VERSION 5.7 ;
  NOWIREEXTENSIONATPIN ON ;
  DIVIDERCHAR "/" ;
  BUSBITCHARS "[]" ;
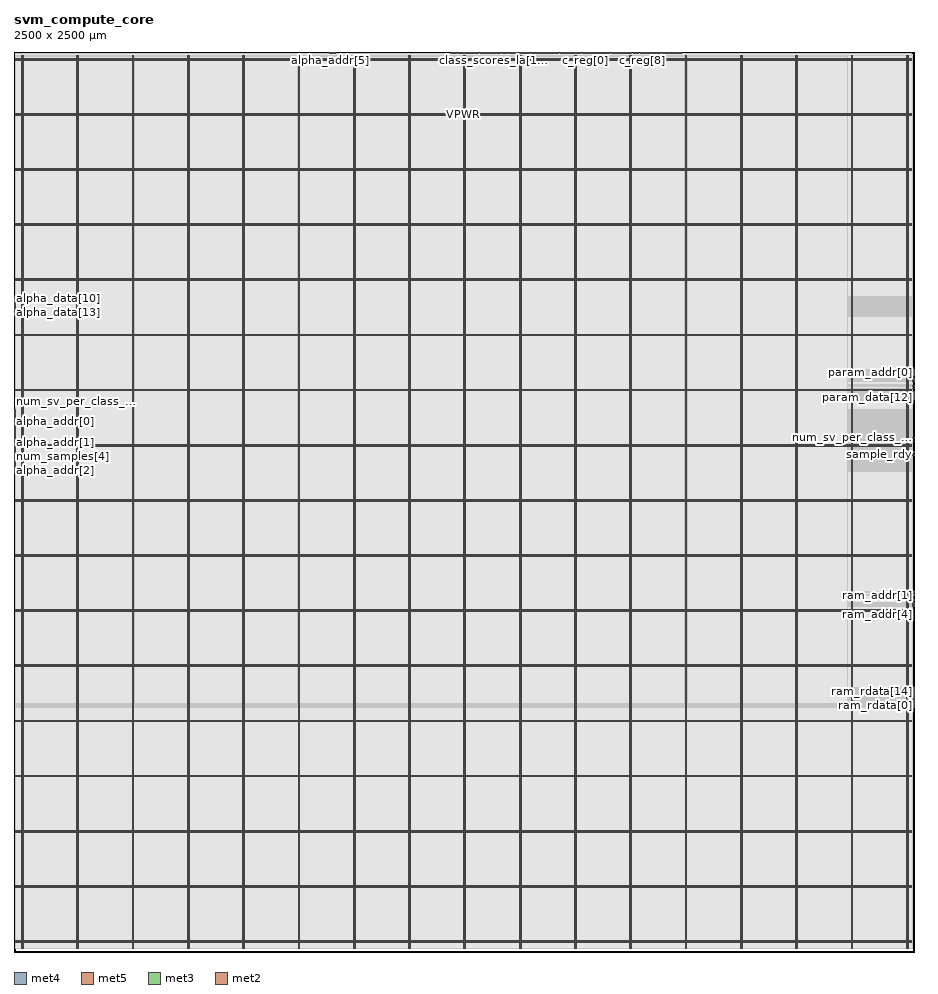
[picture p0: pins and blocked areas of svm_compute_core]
MACRO svm_compute_core
  CLASS BLOCK ;
  FOREIGN svm_compute_core ;
  ORIGIN 0.000 0.000 ;
  SIZE 2500.000 BY 2500.000 ;
  PIN VGND
    DIRECTION INOUT ;
    USE GROUND ;
    PORT
      LAYER met4 ;
        RECT 24.340 10.640 25.940 2489.040 ;
    END
    PORT
      LAYER met4 ;
        RECT 177.940 10.640 179.540 2489.040 ;
    END
    PORT
      LAYER met4 ;
        RECT 331.540 10.640 333.140 2489.040 ;
    END
    PORT
      LAYER met4 ;
        RECT 485.140 10.640 486.740 2489.040 ;
    END
    PORT
      LAYER met4 ;
        RECT 638.740 10.640 640.340 2489.040 ;
    END
    PORT
      LAYER met4 ;
        RECT 792.340 10.640 793.940 2489.040 ;
    END
    PORT
      LAYER met4 ;
        RECT 945.940 10.640 947.540 2489.040 ;
    END
    PORT
      LAYER met4 ;
        RECT 1099.540 10.640 1101.140 2489.040 ;
    END
    PORT
      LAYER met4 ;
        RECT 1253.140 10.640 1254.740 2489.040 ;
    END
    PORT
      LAYER met4 ;
        RECT 1406.740 10.640 1408.340 2489.040 ;
    END
    PORT
      LAYER met4 ;
        RECT 1560.340 10.640 1561.940 2489.040 ;
    END
    PORT
      LAYER met4 ;
        RECT 1713.940 10.640 1715.540 2489.040 ;
    END
    PORT
      LAYER met4 ;
        RECT 1867.540 10.640 1869.140 2489.040 ;
    END
    PORT
      LAYER met4 ;
        RECT 2021.140 10.640 2022.740 2489.040 ;
    END
    PORT
      LAYER met4 ;
        RECT 2174.740 10.640 2176.340 2489.040 ;
    END
    PORT
      LAYER met4 ;
        RECT 2328.340 10.640 2329.940 2489.040 ;
    END
    PORT
      LAYER met4 ;
        RECT 2481.940 10.640 2483.540 2489.040 ;
    END
    PORT
      LAYER met5 ;
        RECT 5.280 30.030 2494.360 31.630 ;
    END
    PORT
      LAYER met5 ;
        RECT 5.280 183.210 2494.360 184.810 ;
    END
    PORT
      LAYER met5 ;
        RECT 5.280 336.390 2494.360 337.990 ;
    END
    PORT
      LAYER met5 ;
        RECT 5.280 489.570 2494.360 491.170 ;
    END
    PORT
      LAYER met5 ;
        RECT 5.280 642.750 2494.360 644.350 ;
    END
    PORT
      LAYER met5 ;
        RECT 5.280 795.930 2494.360 797.530 ;
    END
    PORT
      LAYER met5 ;
        RECT 5.280 949.110 2494.360 950.710 ;
    END
    PORT
      LAYER met5 ;
        RECT 5.280 1102.290 2494.360 1103.890 ;
    END
    PORT
      LAYER met5 ;
        RECT 5.280 1255.470 2494.360 1257.070 ;
    END
    PORT
      LAYER met5 ;
        RECT 5.280 1408.650 2494.360 1410.250 ;
    END
    PORT
      LAYER met5 ;
        RECT 5.280 1561.830 2494.360 1563.430 ;
    END
    PORT
      LAYER met5 ;
        RECT 5.280 1715.010 2494.360 1716.610 ;
    END
    PORT
      LAYER met5 ;
        RECT 5.280 1868.190 2494.360 1869.790 ;
    END
    PORT
      LAYER met5 ;
        RECT 5.280 2021.370 2494.360 2022.970 ;
    END
    PORT
      LAYER met5 ;
        RECT 5.280 2174.550 2494.360 2176.150 ;
    END
    PORT
      LAYER met5 ;
        RECT 5.280 2327.730 2494.360 2329.330 ;
    END
    PORT
      LAYER met5 ;
        RECT 5.280 2480.910 2494.360 2482.510 ;
    END
  END VGND
  PIN VPWR
    DIRECTION INOUT ;
    USE POWER ;
    PORT
      LAYER met4 ;
        RECT 21.040 10.640 22.640 2489.040 ;
    END
    PORT
      LAYER met4 ;
        RECT 174.640 10.640 176.240 2489.040 ;
    END
    PORT
      LAYER met4 ;
        RECT 328.240 10.640 329.840 2489.040 ;
    END
    PORT
      LAYER met4 ;
        RECT 481.840 10.640 483.440 2489.040 ;
    END
    PORT
      LAYER met4 ;
        RECT 635.440 10.640 637.040 2489.040 ;
    END
    PORT
      LAYER met4 ;
        RECT 789.040 10.640 790.640 2489.040 ;
    END
    PORT
      LAYER met4 ;
        RECT 942.640 10.640 944.240 2489.040 ;
    END
    PORT
      LAYER met4 ;
        RECT 1096.240 10.640 1097.840 2489.040 ;
    END
    PORT
      LAYER met4 ;
        RECT 1249.840 10.640 1251.440 2489.040 ;
    END
    PORT
      LAYER met4 ;
        RECT 1403.440 10.640 1405.040 2489.040 ;
    END
    PORT
      LAYER met4 ;
        RECT 1557.040 10.640 1558.640 2489.040 ;
    END
    PORT
      LAYER met4 ;
        RECT 1710.640 10.640 1712.240 2489.040 ;
    END
    PORT
      LAYER met4 ;
        RECT 1864.240 10.640 1865.840 2489.040 ;
    END
    PORT
      LAYER met4 ;
        RECT 2017.840 10.640 2019.440 2489.040 ;
    END
    PORT
      LAYER met4 ;
        RECT 2171.440 10.640 2173.040 2489.040 ;
    END
    PORT
      LAYER met4 ;
        RECT 2325.040 10.640 2326.640 2489.040 ;
    END
    PORT
      LAYER met4 ;
        RECT 2478.640 10.640 2480.240 2489.040 ;
    END
    PORT
      LAYER met5 ;
        RECT 5.280 26.730 2494.360 28.330 ;
    END
    PORT
      LAYER met5 ;
        RECT 5.280 179.910 2494.360 181.510 ;
    END
    PORT
      LAYER met5 ;
        RECT 5.280 333.090 2494.360 334.690 ;
    END
    PORT
      LAYER met5 ;
        RECT 5.280 486.270 2494.360 487.870 ;
    END
    PORT
      LAYER met5 ;
        RECT 5.280 639.450 2494.360 641.050 ;
    END
    PORT
      LAYER met5 ;
        RECT 5.280 792.630 2494.360 794.230 ;
    END
    PORT
      LAYER met5 ;
        RECT 5.280 945.810 2494.360 947.410 ;
    END
    PORT
      LAYER met5 ;
        RECT 5.280 1098.990 2494.360 1100.590 ;
    END
    PORT
      LAYER met5 ;
        RECT 5.280 1252.170 2494.360 1253.770 ;
    END
    PORT
      LAYER met5 ;
        RECT 5.280 1405.350 2494.360 1406.950 ;
    END
    PORT
      LAYER met5 ;
        RECT 5.280 1558.530 2494.360 1560.130 ;
    END
    PORT
      LAYER met5 ;
        RECT 5.280 1711.710 2494.360 1713.310 ;
    END
    PORT
      LAYER met5 ;
        RECT 5.280 1864.890 2494.360 1866.490 ;
    END
    PORT
      LAYER met5 ;
        RECT 5.280 2018.070 2494.360 2019.670 ;
    END
    PORT
      LAYER met5 ;
        RECT 5.280 2171.250 2494.360 2172.850 ;
    END
    PORT
      LAYER met5 ;
        RECT 5.280 2324.430 2494.360 2326.030 ;
    END
    PORT
      LAYER met5 ;
        RECT 5.280 2477.610 2494.360 2479.210 ;
    END
  END VPWR
  PIN alpha_addr[0]
    DIRECTION INPUT ;
    USE SIGNAL ;
    ANTENNAGATEAREA 0.990000 ;
    PORT
      LAYER met3 ;
        RECT 0.000 1472.240 4.000 1472.840 ;
    END
  END alpha_addr[0]
  PIN alpha_addr[1]
    DIRECTION INPUT ;
    USE SIGNAL ;
    ANTENNAGATEAREA 0.990000 ;
    PORT
      LAYER met3 ;
        RECT 0.000 1414.440 4.000 1415.040 ;
    END
  END alpha_addr[1]
  PIN alpha_addr[2]
    DIRECTION INPUT ;
    USE SIGNAL ;
    ANTENNAGATEAREA 0.990000 ;
    PORT
      LAYER met3 ;
        RECT 0.000 1336.240 4.000 1336.840 ;
    END
  END alpha_addr[2]
  PIN alpha_addr[3]
    DIRECTION INPUT ;
    USE SIGNAL ;
    ANTENNAGATEAREA 0.990000 ;
    PORT
      LAYER met3 ;
        RECT 0.000 1356.640 4.000 1357.240 ;
    END
  END alpha_addr[3]
  PIN alpha_addr[4]
    DIRECTION INPUT ;
    USE SIGNAL ;
    ANTENNAGATEAREA 0.742500 ;
    PORT
      LAYER met2 ;
        RECT 875.930 2496.000 876.210 2500.000 ;
    END
  END alpha_addr[4]
  PIN alpha_addr[5]
    DIRECTION INPUT ;
    USE SIGNAL ;
    ANTENNAGATEAREA 0.742500 ;
    PORT
      LAYER met2 ;
        RECT 879.150 2496.000 879.430 2500.000 ;
    END
  END alpha_addr[5]
  PIN alpha_addr[6]
    DIRECTION INPUT ;
    USE SIGNAL ;
    ANTENNAGATEAREA 0.742500 ;
    PORT
      LAYER met2 ;
        RECT 892.030 2496.000 892.310 2500.000 ;
    END
  END alpha_addr[6]
  PIN alpha_addr[7]
    DIRECTION INPUT ;
    USE SIGNAL ;
    ANTENNAGATEAREA 0.742500 ;
    PORT
      LAYER met2 ;
        RECT 888.810 2496.000 889.090 2500.000 ;
    END
  END alpha_addr[7]
  PIN alpha_addr[8]
    DIRECTION INPUT ;
    USE SIGNAL ;
    ANTENNAGATEAREA 0.247500 ;
    PORT
      LAYER met2 ;
        RECT 882.370 2496.000 882.650 2500.000 ;
    END
  END alpha_addr[8]
  PIN alpha_data[0]
    DIRECTION INPUT ;
    USE SIGNAL ;
    ANTENNAGATEAREA 0.852000 ;
    PORT
      LAYER met3 ;
        RECT 0.000 1819.040 4.000 1819.640 ;
    END
  END alpha_data[0]
  PIN alpha_data[10]
    DIRECTION INPUT ;
    USE SIGNAL ;
    ANTENNAGATEAREA 0.990000 ;
    PORT
      LAYER met3 ;
        RECT 0.000 1815.640 4.000 1816.240 ;
    END
  END alpha_data[10]
  PIN alpha_data[11]
    DIRECTION INPUT ;
    USE SIGNAL ;
    ANTENNAGATEAREA 0.990000 ;
    PORT
      LAYER met3 ;
        RECT 0.000 1812.240 4.000 1812.840 ;
    END
  END alpha_data[11]
  PIN alpha_data[12]
    DIRECTION INPUT ;
    USE SIGNAL ;
    ANTENNAGATEAREA 0.852000 ;
    PORT
      LAYER met3 ;
        RECT 0.000 1808.840 4.000 1809.440 ;
    END
  END alpha_data[12]
  PIN alpha_data[13]
    DIRECTION INPUT ;
    USE SIGNAL ;
    ANTENNAGATEAREA 0.495000 ;
    PORT
      LAYER met3 ;
        RECT 0.000 1798.640 4.000 1799.240 ;
    END
  END alpha_data[13]
  PIN alpha_data[14]
    DIRECTION INPUT ;
    USE SIGNAL ;
    ANTENNAGATEAREA 0.852000 ;
    PORT
      LAYER met3 ;
        RECT 0.000 1805.440 4.000 1806.040 ;
    END
  END alpha_data[14]
  PIN alpha_data[15]
    DIRECTION INPUT ;
    USE SIGNAL ;
    ANTENNAGATEAREA 0.990000 ;
    PORT
      LAYER met3 ;
        RECT 0.000 1802.040 4.000 1802.640 ;
    END
  END alpha_data[15]
  PIN alpha_data[1]
    DIRECTION INPUT ;
    USE SIGNAL ;
    ANTENNAGATEAREA 0.990000 ;
    PORT
      LAYER met3 ;
        RECT 0.000 1795.240 4.000 1795.840 ;
    END
  END alpha_data[1]
  PIN alpha_data[2]
    DIRECTION INPUT ;
    USE SIGNAL ;
    ANTENNAGATEAREA 0.990000 ;
    PORT
      LAYER met3 ;
        RECT 0.000 1791.840 4.000 1792.440 ;
    END
  END alpha_data[2]
  PIN alpha_data[3]
    DIRECTION INPUT ;
    USE SIGNAL ;
    ANTENNAGATEAREA 0.990000 ;
    PORT
      LAYER met3 ;
        RECT 0.000 1788.440 4.000 1789.040 ;
    END
  END alpha_data[3]
  PIN alpha_data[4]
    DIRECTION INPUT ;
    USE SIGNAL ;
    ANTENNAGATEAREA 0.990000 ;
    PORT
      LAYER met3 ;
        RECT 0.000 1785.040 4.000 1785.640 ;
    END
  END alpha_data[4]
  PIN alpha_data[5]
    DIRECTION INPUT ;
    USE SIGNAL ;
    ANTENNAGATEAREA 0.990000 ;
    PORT
      LAYER met3 ;
        RECT 0.000 1781.640 4.000 1782.240 ;
    END
  END alpha_data[5]
  PIN alpha_data[6]
    DIRECTION INPUT ;
    USE SIGNAL ;
    ANTENNAGATEAREA 0.990000 ;
    PORT
      LAYER met3 ;
        RECT 0.000 1778.240 4.000 1778.840 ;
    END
  END alpha_data[6]
  PIN alpha_data[7]
    DIRECTION INPUT ;
    USE SIGNAL ;
    ANTENNAGATEAREA 0.990000 ;
    PORT
      LAYER met3 ;
        RECT 0.000 1774.840 4.000 1775.440 ;
    END
  END alpha_data[7]
  PIN alpha_data[8]
    DIRECTION INPUT ;
    USE SIGNAL ;
    ANTENNAGATEAREA 0.247500 ;
    PORT
      LAYER met3 ;
        RECT 0.000 1771.440 4.000 1772.040 ;
    END
  END alpha_data[8]
  PIN alpha_data[9]
    DIRECTION INPUT ;
    USE SIGNAL ;
    ANTENNAGATEAREA 0.852000 ;
    PORT
      LAYER met3 ;
        RECT 0.000 1768.040 4.000 1768.640 ;
    END
  END alpha_data[9]
  PIN alpha_write_en
    DIRECTION INPUT ;
    USE SIGNAL ;
    ANTENNAGATEAREA 0.247500 ;
    PORT
      LAYER met2 ;
        RECT 885.590 2496.000 885.870 2500.000 ;
    END
  END alpha_write_en
  PIN c_reg[0]
    DIRECTION OUTPUT ;
    USE SIGNAL ;
    ANTENNADIFFAREA 0.340600 ;
    PORT
      LAYER met2 ;
        RECT 1587.550 2496.000 1587.830 2500.000 ;
    END
  END c_reg[0]
  PIN c_reg[10]
    DIRECTION OUTPUT ;
    USE SIGNAL ;
    ANTENNADIFFAREA 0.340600 ;
    PORT
      LAYER met2 ;
        RECT 1742.110 2496.000 1742.390 2500.000 ;
    END
  END c_reg[10]
  PIN c_reg[11]
    DIRECTION OUTPUT ;
    USE SIGNAL ;
    ANTENNADIFFAREA 0.340600 ;
    PORT
      LAYER met2 ;
        RECT 1526.370 2496.000 1526.650 2500.000 ;
    END
  END c_reg[11]
  PIN c_reg[12]
    DIRECTION OUTPUT ;
    USE SIGNAL ;
    ANTENNADIFFAREA 0.340600 ;
    PORT
      LAYER met2 ;
        RECT 1548.910 2496.000 1549.190 2500.000 ;
    END
  END c_reg[12]
  PIN c_reg[13]
    DIRECTION OUTPUT ;
    USE SIGNAL ;
    ANTENNADIFFAREA 0.340600 ;
    PORT
      LAYER met2 ;
        RECT 1523.150 2496.000 1523.430 2500.000 ;
    END
  END c_reg[13]
  PIN c_reg[14]
    DIRECTION OUTPUT ;
    USE SIGNAL ;
    ANTENNADIFFAREA 0.340600 ;
    PORT
      LAYER met2 ;
        RECT 1661.610 2496.000 1661.890 2500.000 ;
    END
  END c_reg[14]
  PIN c_reg[15]
    DIRECTION OUTPUT ;
    USE SIGNAL ;
    ANTENNADIFFAREA 0.340600 ;
    PORT
      LAYER met2 ;
        RECT 1703.470 2496.000 1703.750 2500.000 ;
    END
  END c_reg[15]
  PIN c_reg[1]
    DIRECTION OUTPUT ;
    USE SIGNAL ;
    ANTENNADIFFAREA 0.340600 ;
    PORT
      LAYER met2 ;
        RECT 1536.030 2496.000 1536.310 2500.000 ;
    END
  END c_reg[1]
  PIN c_reg[2]
    DIRECTION OUTPUT ;
    USE SIGNAL ;
    ANTENNADIFFAREA 0.340600 ;
    PORT
      LAYER met2 ;
        RECT 1529.590 2496.000 1529.870 2500.000 ;
    END
  END c_reg[2]
  PIN c_reg[3]
    DIRECTION OUTPUT ;
    USE SIGNAL ;
    ANTENNADIFFAREA 0.340600 ;
    PORT
      LAYER met2 ;
        RECT 1532.810 2496.000 1533.090 2500.000 ;
    END
  END c_reg[3]
  PIN c_reg[4]
    DIRECTION OUTPUT ;
    USE SIGNAL ;
    ANTENNADIFFAREA 0.340600 ;
    PORT
      LAYER met2 ;
        RECT 1716.350 2496.000 1716.630 2500.000 ;
    END
  END c_reg[4]
  PIN c_reg[5]
    DIRECTION OUTPUT ;
    USE SIGNAL ;
    ANTENNADIFFAREA 0.340600 ;
    PORT
      LAYER met2 ;
        RECT 1674.490 2496.000 1674.770 2500.000 ;
    END
  END c_reg[5]
  PIN c_reg[6]
    DIRECTION OUTPUT ;
    USE SIGNAL ;
    ANTENNADIFFAREA 0.340600 ;
    PORT
      LAYER met2 ;
        RECT 1568.230 2496.000 1568.510 2500.000 ;
    END
  END c_reg[6]
  PIN c_reg[7]
    DIRECTION OUTPUT ;
    USE SIGNAL ;
    ANTENNADIFFAREA 0.340600 ;
    PORT
      LAYER met2 ;
        RECT 1722.790 2496.000 1723.070 2500.000 ;
    END
  END c_reg[7]
  PIN c_reg[8]
    DIRECTION OUTPUT ;
    USE SIGNAL ;
    ANTENNADIFFAREA 0.340600 ;
    PORT
      LAYER met2 ;
        RECT 1745.330 2496.000 1745.610 2500.000 ;
    END
  END c_reg[8]
  PIN c_reg[9]
    DIRECTION OUTPUT ;
    USE SIGNAL ;
    ANTENNADIFFAREA 0.340600 ;
    PORT
      LAYER met2 ;
        RECT 1726.010 2496.000 1726.290 2500.000 ;
    END
  END c_reg[9]
  PIN class_out[0]
    DIRECTION OUTPUT ;
    USE SIGNAL ;
    ANTENNADIFFAREA 0.340600 ;
    PORT
      LAYER met2 ;
        RECT 1680.930 2496.000 1681.210 2500.000 ;
    END
  END class_out[0]
  PIN class_out[1]
    DIRECTION OUTPUT ;
    USE SIGNAL ;
    ANTENNADIFFAREA 0.340600 ;
    PORT
      LAYER met2 ;
        RECT 1465.190 2496.000 1465.470 2500.000 ;
    END
  END class_out[1]
  PIN class_out[2]
    DIRECTION OUTPUT ;
    USE SIGNAL ;
    ANTENNADIFFAREA 0.340600 ;
    PORT
      LAYER met2 ;
        RECT 1468.410 2496.000 1468.690 2500.000 ;
    END
  END class_out[2]
  PIN class_scores_la[0]
    DIRECTION OUTPUT ;
    USE SIGNAL ;
    ANTENNADIFFAREA 0.340600 ;
    PORT
      LAYER met2 ;
        RECT 1658.390 2496.000 1658.670 2500.000 ;
    END
  END class_scores_la[0]
  PIN class_scores_la[100]
    DIRECTION OUTPUT ;
    USE SIGNAL ;
    ANTENNADIFFAREA 0.340600 ;
    PORT
      LAYER met2 ;
        RECT 1539.250 2496.000 1539.530 2500.000 ;
    END
  END class_scores_la[100]
  PIN class_scores_la[101]
    DIRECTION OUTPUT ;
    USE SIGNAL ;
    ANTENNADIFFAREA 0.340600 ;
    PORT
      LAYER met2 ;
        RECT 1664.830 2496.000 1665.110 2500.000 ;
    END
  END class_scores_la[101]
  PIN class_scores_la[102]
    DIRECTION OUTPUT ;
    USE SIGNAL ;
    ANTENNADIFFAREA 0.340600 ;
    PORT
      LAYER met2 ;
        RECT 1478.070 2496.000 1478.350 2500.000 ;
    END
  END class_scores_la[102]
  PIN class_scores_la[103]
    DIRECTION OUTPUT ;
    USE SIGNAL ;
    ANTENNADIFFAREA 0.340600 ;
    PORT
      LAYER met2 ;
        RECT 1439.430 2496.000 1439.710 2500.000 ;
    END
  END class_scores_la[103]
  PIN class_scores_la[104]
    DIRECTION OUTPUT ;
    USE SIGNAL ;
    ANTENNADIFFAREA 0.340600 ;
    PORT
      LAYER met2 ;
        RECT 1848.370 2496.000 1848.650 2500.000 ;
    END
  END class_scores_la[104]
  PIN class_scores_la[105]
    DIRECTION OUTPUT ;
    USE SIGNAL ;
    ANTENNADIFFAREA 0.340600 ;
    PORT
      LAYER met2 ;
        RECT 1835.490 2496.000 1835.770 2500.000 ;
    END
  END class_scores_la[105]
  PIN class_scores_la[106]
    DIRECTION OUTPUT ;
    USE SIGNAL ;
    ANTENNADIFFAREA 0.340600 ;
    PORT
      LAYER met2 ;
        RECT 1622.970 2496.000 1623.250 2500.000 ;
    END
  END class_scores_la[106]
  PIN class_scores_la[107]
    DIRECTION OUTPUT ;
    USE SIGNAL ;
    ANTENNADIFFAREA 0.340600 ;
    PORT
      LAYER met2 ;
        RECT 1487.730 2496.000 1488.010 2500.000 ;
    END
  END class_scores_la[107]
  PIN class_scores_la[108]
    DIRECTION OUTPUT ;
    USE SIGNAL ;
    ANTENNADIFFAREA 0.340600 ;
    PORT
      LAYER met2 ;
        RECT 1442.650 2496.000 1442.930 2500.000 ;
    END
  END class_scores_la[108]
  PIN class_scores_la[109]
    DIRECTION OUTPUT ;
    USE SIGNAL ;
    ANTENNADIFFAREA 0.340600 ;
    PORT
      LAYER met2 ;
        RECT 1484.510 2496.000 1484.790 2500.000 ;
    END
  END class_scores_la[109]
  PIN class_scores_la[10]
    DIRECTION OUTPUT ;
    USE SIGNAL ;
    ANTENNADIFFAREA 0.340600 ;
    PORT
      LAYER met2 ;
        RECT 1635.850 2496.000 1636.130 2500.000 ;
    END
  END class_scores_la[10]
  PIN class_scores_la[110]
    DIRECTION OUTPUT ;
    USE SIGNAL ;
    ANTENNADIFFAREA 0.340600 ;
    PORT
      LAYER met2 ;
        RECT 1423.330 2496.000 1423.610 2500.000 ;
    END
  END class_scores_la[110]
  PIN class_scores_la[111]
    DIRECTION OUTPUT ;
    USE SIGNAL ;
    ANTENNADIFFAREA 0.340600 ;
    PORT
      LAYER met2 ;
        RECT 1394.350 2496.000 1394.630 2500.000 ;
    END
  END class_scores_la[111]
  PIN class_scores_la[112]
    DIRECTION OUTPUT ;
    USE SIGNAL ;
    ANTENNADIFFAREA 0.340600 ;
    PORT
      LAYER met2 ;
        RECT 1774.310 2496.000 1774.590 2500.000 ;
    END
  END class_scores_la[112]
  PIN class_scores_la[113]
    DIRECTION OUTPUT ;
    USE SIGNAL ;
    ANTENNADIFFAREA 0.340600 ;
    PORT
      LAYER met2 ;
        RECT 1404.010 2496.000 1404.290 2500.000 ;
    END
  END class_scores_la[113]
  PIN class_scores_la[114]
    DIRECTION OUTPUT ;
    USE SIGNAL ;
    ANTENNADIFFAREA 0.340600 ;
    PORT
      LAYER met2 ;
        RECT 1387.910 2496.000 1388.190 2500.000 ;
    END
  END class_scores_la[114]
  PIN class_scores_la[115]
    DIRECTION OUTPUT ;
    USE SIGNAL ;
    ANTENNADIFFAREA 0.340600 ;
    PORT
      LAYER met2 ;
        RECT 1333.170 2496.000 1333.450 2500.000 ;
    END
  END class_scores_la[115]
  PIN class_scores_la[116]
    DIRECTION OUTPUT ;
    USE SIGNAL ;
    ANTENNADIFFAREA 0.340600 ;
    PORT
      LAYER met2 ;
        RECT 1365.370 2496.000 1365.650 2500.000 ;
    END
  END class_scores_la[116]
  PIN class_scores_la[117]
    DIRECTION OUTPUT ;
    USE SIGNAL ;
    ANTENNADIFFAREA 0.340600 ;
    PORT
      LAYER met2 ;
        RECT 1416.890 2496.000 1417.170 2500.000 ;
    END
  END class_scores_la[117]
  PIN class_scores_la[118]
    DIRECTION OUTPUT ;
    USE SIGNAL ;
    ANTENNADIFFAREA 0.340600 ;
    PORT
      LAYER met2 ;
        RECT 1429.770 2496.000 1430.050 2500.000 ;
    END
  END class_scores_la[118]
  PIN class_scores_la[119]
    DIRECTION OUTPUT ;
    USE SIGNAL ;
    ANTENNADIFFAREA 0.340600 ;
    PORT
      LAYER met2 ;
        RECT 1436.210 2496.000 1436.490 2500.000 ;
    END
  END class_scores_la[119]
  PIN class_scores_la[11]
    DIRECTION OUTPUT ;
    USE SIGNAL ;
    ANTENNADIFFAREA 0.340600 ;
    PORT
      LAYER met2 ;
        RECT 1494.170 2496.000 1494.450 2500.000 ;
    END
  END class_scores_la[11]
  PIN class_scores_la[120]
    DIRECTION OUTPUT ;
    USE SIGNAL ;
    ANTENNADIFFAREA 0.340600 ;
    PORT
      LAYER met2 ;
        RECT 1452.310 2496.000 1452.590 2500.000 ;
    END
  END class_scores_la[120]
  PIN class_scores_la[121]
    DIRECTION OUTPUT ;
    USE SIGNAL ;
    ANTENNADIFFAREA 0.340600 ;
    PORT
      LAYER met2 ;
        RECT 1632.630 2496.000 1632.910 2500.000 ;
    END
  END class_scores_la[121]
  PIN class_scores_la[122]
    DIRECTION OUTPUT ;
    USE SIGNAL ;
    ANTENNADIFFAREA 0.340600 ;
    PORT
      LAYER met2 ;
        RECT 1796.850 2496.000 1797.130 2500.000 ;
    END
  END class_scores_la[122]
  PIN class_scores_la[123]
    DIRECTION OUTPUT ;
    USE SIGNAL ;
    ANTENNADIFFAREA 0.340600 ;
    PORT
      LAYER met2 ;
        RECT 1581.110 2496.000 1581.390 2500.000 ;
    END
  END class_scores_la[123]
  PIN class_scores_la[124]
    DIRECTION OUTPUT ;
    USE SIGNAL ;
    ANTENNADIFFAREA 0.340600 ;
    PORT
      LAYER met2 ;
        RECT 1790.410 2496.000 1790.690 2500.000 ;
    END
  END class_scores_la[124]
  PIN class_scores_la[125]
    DIRECTION OUTPUT ;
    USE SIGNAL ;
    ANTENNADIFFAREA 0.340600 ;
    PORT
      LAYER met2 ;
        RECT 1571.450 2496.000 1571.730 2500.000 ;
    END
  END class_scores_la[125]
  PIN class_scores_la[126]
    DIRECTION OUTPUT ;
    USE SIGNAL ;
    ANTENNADIFFAREA 0.340600 ;
    PORT
      LAYER met2 ;
        RECT 1764.650 2496.000 1764.930 2500.000 ;
    END
  END class_scores_la[126]
  PIN class_scores_la[127]
    DIRECTION OUTPUT ;
    USE SIGNAL ;
    ANTENNADIFFAREA 0.340600 ;
    PORT
      LAYER met2 ;
        RECT 1626.190 2496.000 1626.470 2500.000 ;
    END
  END class_scores_la[127]
  PIN class_scores_la[12]
    DIRECTION OUTPUT ;
    USE SIGNAL ;
    ANTENNADIFFAREA 0.340600 ;
    PORT
      LAYER met2 ;
        RECT 1713.130 2496.000 1713.410 2500.000 ;
    END
  END class_scores_la[12]
  PIN class_scores_la[13]
    DIRECTION OUTPUT ;
    USE SIGNAL ;
    ANTENNADIFFAREA 0.340600 ;
    PORT
      LAYER met2 ;
        RECT 1648.730 2496.000 1649.010 2500.000 ;
    END
  END class_scores_la[13]
  PIN class_scores_la[14]
    DIRECTION OUTPUT ;
    USE SIGNAL ;
    ANTENNADIFFAREA 0.340600 ;
    PORT
      LAYER met2 ;
        RECT 1458.750 2496.000 1459.030 2500.000 ;
    END
  END class_scores_la[14]
  PIN class_scores_la[15]
    DIRECTION OUTPUT ;
    USE SIGNAL ;
    ANTENNADIFFAREA 0.340600 ;
    PORT
      LAYER met2 ;
        RECT 1577.890 2496.000 1578.170 2500.000 ;
    END
  END class_scores_la[15]
  PIN class_scores_la[16]
    DIRECTION OUTPUT ;
    USE SIGNAL ;
    ANTENNADIFFAREA 0.340600 ;
    PORT
      LAYER met2 ;
        RECT 1825.830 2496.000 1826.110 2500.000 ;
    END
  END class_scores_la[16]
  PIN class_scores_la[17]
    DIRECTION OUTPUT ;
    USE SIGNAL ;
    ANTENNADIFFAREA 0.340600 ;
    PORT
      LAYER met2 ;
        RECT 1259.110 2496.000 1259.390 2500.000 ;
    END
  END class_scores_la[17]
  PIN class_scores_la[18]
    DIRECTION OUTPUT ;
    USE SIGNAL ;
    ANTENNADIFFAREA 0.340600 ;
    PORT
      LAYER met2 ;
        RECT 1339.610 2496.000 1339.890 2500.000 ;
    END
  END class_scores_la[18]
  PIN class_scores_la[19]
    DIRECTION OUTPUT ;
    USE SIGNAL ;
    ANTENNADIFFAREA 0.340600 ;
    PORT
      LAYER met2 ;
        RECT 1384.690 2496.000 1384.970 2500.000 ;
    END
  END class_scores_la[19]
  PIN class_scores_la[1]
    DIRECTION OUTPUT ;
    USE SIGNAL ;
    ANTENNADIFFAREA 0.340600 ;
    PORT
      LAYER met2 ;
        RECT 1461.970 2496.000 1462.250 2500.000 ;
    END
  END class_scores_la[1]
  PIN class_scores_la[20]
    DIRECTION OUTPUT ;
    USE SIGNAL ;
    ANTENNADIFFAREA 0.340600 ;
    PORT
      LAYER met2 ;
        RECT 1294.530 2496.000 1294.810 2500.000 ;
    END
  END class_scores_la[20]
  PIN class_scores_la[21]
    DIRECTION OUTPUT ;
    USE SIGNAL ;
    ANTENNADIFFAREA 0.340600 ;
    PORT
      LAYER met2 ;
        RECT 1410.450 2496.000 1410.730 2500.000 ;
    END
  END class_scores_la[21]
  PIN class_scores_la[22]
    DIRECTION OUTPUT ;
    USE SIGNAL ;
    ANTENNADIFFAREA 0.340600 ;
    PORT
      LAYER met2 ;
        RECT 1420.110 2496.000 1420.390 2500.000 ;
    END
  END class_scores_la[22]
  PIN class_scores_la[23]
    DIRECTION OUTPUT ;
    USE SIGNAL ;
    ANTENNADIFFAREA 0.340600 ;
    PORT
      LAYER met2 ;
        RECT 1832.270 2496.000 1832.550 2500.000 ;
    END
  END class_scores_la[23]
  PIN class_scores_la[24]
    DIRECTION OUTPUT ;
    USE SIGNAL ;
    ANTENNADIFFAREA 0.340600 ;
    PORT
      LAYER met2 ;
        RECT 1558.570 2496.000 1558.850 2500.000 ;
    END
  END class_scores_la[24]
  PIN class_scores_la[25]
    DIRECTION OUTPUT ;
    USE SIGNAL ;
    ANTENNADIFFAREA 0.340600 ;
    PORT
      LAYER met2 ;
        RECT 1806.510 2496.000 1806.790 2500.000 ;
    END
  END class_scores_la[25]
  PIN class_scores_la[26]
    DIRECTION OUTPUT ;
    USE SIGNAL ;
    ANTENNADIFFAREA 0.340600 ;
    PORT
      LAYER met2 ;
        RECT 1542.470 2496.000 1542.750 2500.000 ;
    END
  END class_scores_la[26]
  PIN class_scores_la[27]
    DIRECTION OUTPUT ;
    USE SIGNAL ;
    ANTENNADIFFAREA 0.340600 ;
    PORT
      LAYER met2 ;
        RECT 1803.290 2496.000 1803.570 2500.000 ;
    END
  END class_scores_la[27]
  PIN class_scores_la[28]
    DIRECTION OUTPUT ;
    USE SIGNAL ;
    ANTENNADIFFAREA 0.340600 ;
    PORT
      LAYER met2 ;
        RECT 1668.050 2496.000 1668.330 2500.000 ;
    END
  END class_scores_la[28]
  PIN class_scores_la[29]
    DIRECTION OUTPUT ;
    USE SIGNAL ;
    ANTENNADIFFAREA 0.340600 ;
    PORT
      LAYER met2 ;
        RECT 1590.770 2496.000 1591.050 2500.000 ;
    END
  END class_scores_la[29]
  PIN class_scores_la[2]
    DIRECTION OUTPUT ;
    USE SIGNAL ;
    ANTENNADIFFAREA 0.340600 ;
    PORT
      LAYER met2 ;
        RECT 1323.510 2496.000 1323.790 2500.000 ;
    END
  END class_scores_la[2]
  PIN class_scores_la[30]
    DIRECTION OUTPUT ;
    USE SIGNAL ;
    ANTENNADIFFAREA 0.340600 ;
    PORT
      LAYER met2 ;
        RECT 1738.890 2496.000 1739.170 2500.000 ;
    END
  END class_scores_la[30]
  PIN class_scores_la[31]
    DIRECTION OUTPUT ;
    USE SIGNAL ;
    ANTENNADIFFAREA 0.340600 ;
    PORT
      LAYER met2 ;
        RECT 1555.350 2496.000 1555.630 2500.000 ;
    END
  END class_scores_la[31]
  PIN class_scores_la[32]
    DIRECTION OUTPUT ;
    USE SIGNAL ;
    ANTENNADIFFAREA 0.340600 ;
    PORT
      LAYER met2 ;
        RECT 1471.630 2496.000 1471.910 2500.000 ;
    END
  END class_scores_la[32]
  PIN class_scores_la[33]
    DIRECTION OUTPUT ;
    USE SIGNAL ;
    ANTENNADIFFAREA 0.340600 ;
    PORT
      LAYER met2 ;
        RECT 1613.310 2496.000 1613.590 2500.000 ;
    END
  END class_scores_la[33]
  PIN class_scores_la[34]
    DIRECTION OUTPUT ;
    USE SIGNAL ;
    ANTENNADIFFAREA 0.340600 ;
    PORT
      LAYER met2 ;
        RECT 1371.810 2496.000 1372.090 2500.000 ;
    END
  END class_scores_la[34]
  PIN class_scores_la[35]
    DIRECTION OUTPUT ;
    USE SIGNAL ;
    ANTENNADIFFAREA 0.340600 ;
    PORT
      LAYER met2 ;
        RECT 1761.430 2496.000 1761.710 2500.000 ;
    END
  END class_scores_la[35]
  PIN class_scores_la[36]
    DIRECTION OUTPUT ;
    USE SIGNAL ;
    ANTENNADIFFAREA 0.340600 ;
    PORT
      LAYER met2 ;
        RECT 1500.610 2496.000 1500.890 2500.000 ;
    END
  END class_scores_la[36]
  PIN class_scores_la[37]
    DIRECTION OUTPUT ;
    USE SIGNAL ;
    ANTENNADIFFAREA 0.340600 ;
    PORT
      LAYER met2 ;
        RECT 1516.710 2496.000 1516.990 2500.000 ;
    END
  END class_scores_la[37]
  PIN class_scores_la[38]
    DIRECTION OUTPUT ;
    USE SIGNAL ;
    ANTENNADIFFAREA 0.340600 ;
    PORT
      LAYER met2 ;
        RECT 1507.050 2496.000 1507.330 2500.000 ;
    END
  END class_scores_la[38]
  PIN class_scores_la[39]
    DIRECTION OUTPUT ;
    USE SIGNAL ;
    ANTENNADIFFAREA 0.340600 ;
    PORT
      LAYER met2 ;
        RECT 1809.730 2496.000 1810.010 2500.000 ;
    END
  END class_scores_la[39]
  PIN class_scores_la[3]
    DIRECTION OUTPUT ;
    USE SIGNAL ;
    ANTENNADIFFAREA 0.340600 ;
    PORT
      LAYER met2 ;
        RECT 1854.810 2496.000 1855.090 2500.000 ;
    END
  END class_scores_la[3]
  PIN class_scores_la[40]
    DIRECTION OUTPUT ;
    USE SIGNAL ;
    ANTENNADIFFAREA 0.340600 ;
    PORT
      LAYER met2 ;
        RECT 1780.750 2496.000 1781.030 2500.000 ;
    END
  END class_scores_la[40]
  PIN class_scores_la[41]
    DIRECTION OUTPUT ;
    USE SIGNAL ;
    ANTENNADIFFAREA 0.340600 ;
    PORT
      LAYER met2 ;
        RECT 1684.150 2496.000 1684.430 2500.000 ;
    END
  END class_scores_la[41]
  PIN class_scores_la[42]
    DIRECTION OUTPUT ;
    USE SIGNAL ;
    ANTENNADIFFAREA 0.340600 ;
    PORT
      LAYER met2 ;
        RECT 1706.690 2496.000 1706.970 2500.000 ;
    END
  END class_scores_la[42]
  PIN class_scores_la[43]
    DIRECTION OUTPUT ;
    USE SIGNAL ;
    ANTENNADIFFAREA 0.340600 ;
    PORT
      LAYER met2 ;
        RECT 1510.270 2496.000 1510.550 2500.000 ;
    END
  END class_scores_la[43]
  PIN class_scores_la[44]
    DIRECTION OUTPUT ;
    USE SIGNAL ;
    ANTENNADIFFAREA 0.340600 ;
    PORT
      LAYER met2 ;
        RECT 1474.850 2496.000 1475.130 2500.000 ;
    END
  END class_scores_la[44]
  PIN class_scores_la[45]
    DIRECTION OUTPUT ;
    USE SIGNAL ;
    ANTENNADIFFAREA 0.340600 ;
    PORT
      LAYER met2 ;
        RECT 1490.950 2496.000 1491.230 2500.000 ;
    END
  END class_scores_la[45]
  PIN class_scores_la[46]
    DIRECTION OUTPUT ;
    USE SIGNAL ;
    ANTENNADIFFAREA 0.340600 ;
    PORT
      LAYER met2 ;
        RECT 1783.970 2496.000 1784.250 2500.000 ;
    END
  END class_scores_la[46]
  PIN class_scores_la[47]
    DIRECTION OUTPUT ;
    USE SIGNAL ;
    ANTENNADIFFAREA 0.340600 ;
    PORT
      LAYER met2 ;
        RECT 1822.610 2496.000 1822.890 2500.000 ;
    END
  END class_scores_la[47]
  PIN class_scores_la[48]
    DIRECTION OUTPUT ;
    USE SIGNAL ;
    ANTENNADIFFAREA 0.340600 ;
    PORT
      LAYER met2 ;
        RECT 1552.130 2496.000 1552.410 2500.000 ;
    END
  END class_scores_la[48]
  PIN class_scores_la[49]
    DIRECTION OUTPUT ;
    USE SIGNAL ;
    ANTENNADIFFAREA 0.340600 ;
    PORT
      LAYER met2 ;
        RECT 1310.630 2496.000 1310.910 2500.000 ;
    END
  END class_scores_la[49]
  PIN class_scores_la[4]
    DIRECTION OUTPUT ;
    USE SIGNAL ;
    ANTENNADIFFAREA 0.340600 ;
    PORT
      LAYER met2 ;
        RECT 1503.830 2496.000 1504.110 2500.000 ;
    END
  END class_scores_la[4]
  PIN class_scores_la[50]
    DIRECTION OUTPUT ;
    USE SIGNAL ;
    ANTENNADIFFAREA 0.340600 ;
    PORT
      LAYER met2 ;
        RECT 1291.310 2496.000 1291.590 2500.000 ;
    END
  END class_scores_la[50]
  PIN class_scores_la[51]
    DIRECTION OUTPUT ;
    USE SIGNAL ;
    ANTENNADIFFAREA 0.340600 ;
    PORT
      LAYER met2 ;
        RECT 1246.230 2496.000 1246.510 2500.000 ;
    END
  END class_scores_la[51]
  PIN class_scores_la[52]
    DIRECTION OUTPUT ;
    USE SIGNAL ;
    ANTENNADIFFAREA 0.340600 ;
    PORT
      LAYER met2 ;
        RECT 1352.490 2496.000 1352.770 2500.000 ;
    END
  END class_scores_la[52]
  PIN class_scores_la[53]
    DIRECTION OUTPUT ;
    USE SIGNAL ;
    ANTENNADIFFAREA 0.340600 ;
    PORT
      LAYER met2 ;
        RECT 1400.790 2496.000 1401.070 2500.000 ;
    END
  END class_scores_la[53]
  PIN class_scores_la[54]
    DIRECTION OUTPUT ;
    USE SIGNAL ;
    ANTENNADIFFAREA 0.340600 ;
    PORT
      LAYER met2 ;
        RECT 1426.550 2496.000 1426.830 2500.000 ;
    END
  END class_scores_la[54]
  PIN class_scores_la[55]
    DIRECTION OUTPUT ;
    USE SIGNAL ;
    ANTENNADIFFAREA 0.340600 ;
    PORT
      LAYER met2 ;
        RECT 1432.990 2496.000 1433.270 2500.000 ;
    END
  END class_scores_la[55]
  PIN class_scores_la[56]
    DIRECTION OUTPUT ;
    USE SIGNAL ;
    ANTENNADIFFAREA 0.340600 ;
    PORT
      LAYER met2 ;
        RECT 1445.870 2496.000 1446.150 2500.000 ;
    END
  END class_scores_la[56]
  PIN class_scores_la[57]
    DIRECTION OUTPUT ;
    USE SIGNAL ;
    ANTENNADIFFAREA 0.340600 ;
    PORT
      LAYER met2 ;
        RECT 1812.950 2496.000 1813.230 2500.000 ;
    END
  END class_scores_la[57]
  PIN class_scores_la[58]
    DIRECTION OUTPUT ;
    USE SIGNAL ;
    ANTENNADIFFAREA 0.340600 ;
    PORT
      LAYER met2 ;
        RECT 1787.190 2496.000 1787.470 2500.000 ;
    END
  END class_scores_la[58]
  PIN class_scores_la[59]
    DIRECTION OUTPUT ;
    USE SIGNAL ;
    ANTENNADIFFAREA 0.340600 ;
    PORT
      LAYER met2 ;
        RECT 1593.990 2496.000 1594.270 2500.000 ;
    END
  END class_scores_la[59]
  PIN class_scores_la[5]
    DIRECTION OUTPUT ;
    USE SIGNAL ;
    ANTENNADIFFAREA 0.340600 ;
    PORT
      LAYER met2 ;
        RECT 1687.370 2496.000 1687.650 2500.000 ;
    END
  END class_scores_la[5]
  PIN class_scores_la[60]
    DIRECTION OUTPUT ;
    USE SIGNAL ;
    ANTENNADIFFAREA 0.340600 ;
    PORT
      LAYER met2 ;
        RECT 1545.690 2496.000 1545.970 2500.000 ;
    END
  END class_scores_la[60]
  PIN class_scores_la[61]
    DIRECTION OUTPUT ;
    USE SIGNAL ;
    ANTENNADIFFAREA 0.340600 ;
    PORT
      LAYER met2 ;
        RECT 1574.670 2496.000 1574.950 2500.000 ;
    END
  END class_scores_la[61]
  PIN class_scores_la[62]
    DIRECTION OUTPUT ;
    USE SIGNAL ;
    ANTENNADIFFAREA 0.340600 ;
    PORT
      LAYER met2 ;
        RECT 1603.650 2496.000 1603.930 2500.000 ;
    END
  END class_scores_la[62]
  PIN class_scores_la[63]
    DIRECTION OUTPUT ;
    USE SIGNAL ;
    ANTENNADIFFAREA 0.340600 ;
    PORT
      LAYER met2 ;
        RECT 1729.230 2496.000 1729.510 2500.000 ;
    END
  END class_scores_la[63]
  PIN class_scores_la[64]
    DIRECTION OUTPUT ;
    USE SIGNAL ;
    ANTENNADIFFAREA 0.340600 ;
    PORT
      LAYER met2 ;
        RECT 1481.290 2496.000 1481.570 2500.000 ;
    END
  END class_scores_la[64]
  PIN class_scores_la[65]
    DIRECTION OUTPUT ;
    USE SIGNAL ;
    ANTENNADIFFAREA 0.340600 ;
    PORT
      LAYER met2 ;
        RECT 1616.530 2496.000 1616.810 2500.000 ;
    END
  END class_scores_la[65]
  PIN class_scores_la[66]
    DIRECTION OUTPUT ;
    USE SIGNAL ;
    ANTENNADIFFAREA 0.340600 ;
    PORT
      LAYER met2 ;
        RECT 1317.070 2496.000 1317.350 2500.000 ;
    END
  END class_scores_la[66]
  PIN class_scores_la[67]
    DIRECTION OUTPUT ;
    USE SIGNAL ;
    ANTENNADIFFAREA 0.340600 ;
    PORT
      LAYER met2 ;
        RECT 1754.990 2496.000 1755.270 2500.000 ;
    END
  END class_scores_la[67]
  PIN class_scores_la[68]
    DIRECTION OUTPUT ;
    USE SIGNAL ;
    ANTENNADIFFAREA 0.340600 ;
    PORT
      LAYER met2 ;
        RECT 1519.930 2496.000 1520.210 2500.000 ;
    END
  END class_scores_la[68]
  PIN class_scores_la[69]
    DIRECTION OUTPUT ;
    USE SIGNAL ;
    ANTENNADIFFAREA 0.340600 ;
    PORT
      LAYER met2 ;
        RECT 1748.550 2496.000 1748.830 2500.000 ;
    END
  END class_scores_la[69]
  PIN class_scores_la[6]
    DIRECTION OUTPUT ;
    USE SIGNAL ;
    ANTENNADIFFAREA 0.340600 ;
    PORT
      LAYER met2 ;
        RECT 1513.490 2496.000 1513.770 2500.000 ;
    END
  END class_scores_la[6]
  PIN class_scores_la[70]
    DIRECTION OUTPUT ;
    USE SIGNAL ;
    ANTENNADIFFAREA 0.340600 ;
    PORT
      LAYER met2 ;
        RECT 1700.250 2496.000 1700.530 2500.000 ;
    END
  END class_scores_la[70]
  PIN class_scores_la[71]
    DIRECTION OUTPUT ;
    USE SIGNAL ;
    ANTENNADIFFAREA 0.340600 ;
    PORT
      LAYER met2 ;
        RECT 1819.390 2496.000 1819.670 2500.000 ;
    END
  END class_scores_la[71]
  PIN class_scores_la[72]
    DIRECTION OUTPUT ;
    USE SIGNAL ;
    ANTENNADIFFAREA 0.340600 ;
    PORT
      LAYER met2 ;
        RECT 1851.590 2496.000 1851.870 2500.000 ;
    END
  END class_scores_la[72]
  PIN class_scores_la[73]
    DIRECTION OUTPUT ;
    USE SIGNAL ;
    ANTENNADIFFAREA 0.340600 ;
    PORT
      LAYER met2 ;
        RECT 1671.270 2496.000 1671.550 2500.000 ;
    END
  END class_scores_la[73]
  PIN class_scores_la[74]
    DIRECTION OUTPUT ;
    USE SIGNAL ;
    ANTENNADIFFAREA 0.340600 ;
    PORT
      LAYER met2 ;
        RECT 1767.870 2496.000 1768.150 2500.000 ;
    END
  END class_scores_la[74]
  PIN class_scores_la[75]
    DIRECTION OUTPUT ;
    USE SIGNAL ;
    ANTENNADIFFAREA 0.340600 ;
    PORT
      LAYER met2 ;
        RECT 1771.090 2496.000 1771.370 2500.000 ;
    END
  END class_scores_la[75]
  PIN class_scores_la[76]
    DIRECTION OUTPUT ;
    USE SIGNAL ;
    ANTENNADIFFAREA 0.340600 ;
    PORT
      LAYER met2 ;
        RECT 1455.530 2496.000 1455.810 2500.000 ;
    END
  END class_scores_la[76]
  PIN class_scores_la[77]
    DIRECTION OUTPUT ;
    USE SIGNAL ;
    ANTENNADIFFAREA 0.340600 ;
    PORT
      LAYER met2 ;
        RECT 1497.390 2496.000 1497.670 2500.000 ;
    END
  END class_scores_la[77]
  PIN class_scores_la[78]
    DIRECTION OUTPUT ;
    USE SIGNAL ;
    ANTENNADIFFAREA 0.340600 ;
    PORT
      LAYER met2 ;
        RECT 1449.090 2496.000 1449.370 2500.000 ;
    END
  END class_scores_la[78]
  PIN class_scores_la[79]
    DIRECTION OUTPUT ;
    USE SIGNAL ;
    ANTENNADIFFAREA 0.340600 ;
    PORT
      LAYER met2 ;
        RECT 1845.150 2496.000 1845.430 2500.000 ;
    END
  END class_scores_la[79]
  PIN class_scores_la[7]
    DIRECTION OUTPUT ;
    USE SIGNAL ;
    ANTENNADIFFAREA 0.340600 ;
    PORT
      LAYER met2 ;
        RECT 1584.330 2496.000 1584.610 2500.000 ;
    END
  END class_scores_la[7]
  PIN class_scores_la[80]
    DIRECTION OUTPUT ;
    USE SIGNAL ;
    ANTENNADIFFAREA 0.340600 ;
    PORT
      LAYER met2 ;
        RECT 1829.050 2496.000 1829.330 2500.000 ;
    END
  END class_scores_la[80]
  PIN class_scores_la[81]
    DIRECTION OUTPUT ;
    USE SIGNAL ;
    ANTENNADIFFAREA 0.340600 ;
    PORT
      LAYER met2 ;
        RECT 1407.230 2496.000 1407.510 2500.000 ;
    END
  END class_scores_la[81]
  PIN class_scores_la[82]
    DIRECTION OUTPUT ;
    USE SIGNAL ;
    ANTENNADIFFAREA 0.340600 ;
    PORT
      LAYER met2 ;
        RECT 1355.710 2496.000 1355.990 2500.000 ;
    END
  END class_scores_la[82]
  PIN class_scores_la[83]
    DIRECTION OUTPUT ;
    USE SIGNAL ;
    ANTENNADIFFAREA 0.340600 ;
    PORT
      LAYER met2 ;
        RECT 1368.590 2496.000 1368.870 2500.000 ;
    END
  END class_scores_la[83]
  PIN class_scores_la[84]
    DIRECTION OUTPUT ;
    USE SIGNAL ;
    ANTENNADIFFAREA 0.340600 ;
    PORT
      LAYER met2 ;
        RECT 1378.250 2496.000 1378.530 2500.000 ;
    END
  END class_scores_la[84]
  PIN class_scores_la[85]
    DIRECTION OUTPUT ;
    USE SIGNAL ;
    ANTENNADIFFAREA 0.340600 ;
    PORT
      LAYER met2 ;
        RECT 1397.570 2496.000 1397.850 2500.000 ;
    END
  END class_scores_la[85]
  PIN class_scores_la[86]
    DIRECTION OUTPUT ;
    USE SIGNAL ;
    ANTENNADIFFAREA 0.340600 ;
    PORT
      LAYER met2 ;
        RECT 1413.670 2496.000 1413.950 2500.000 ;
    END
  END class_scores_la[86]
  PIN class_scores_la[87]
    DIRECTION OUTPUT ;
    USE SIGNAL ;
    ANTENNADIFFAREA 0.340600 ;
    PORT
      LAYER met2 ;
        RECT 1838.710 2496.000 1838.990 2500.000 ;
    END
  END class_scores_la[87]
  PIN class_scores_la[88]
    DIRECTION OUTPUT ;
    USE SIGNAL ;
    ANTENNADIFFAREA 0.340600 ;
    PORT
      LAYER met2 ;
        RECT 1816.170 2496.000 1816.450 2500.000 ;
    END
  END class_scores_la[88]
  PIN class_scores_la[89]
    DIRECTION OUTPUT ;
    USE SIGNAL ;
    ANTENNADIFFAREA 0.340600 ;
    PORT
      LAYER met2 ;
        RECT 1841.930 2496.000 1842.210 2500.000 ;
    END
  END class_scores_la[89]
  PIN class_scores_la[8]
    DIRECTION OUTPUT ;
    USE SIGNAL ;
    ANTENNADIFFAREA 0.340600 ;
    PORT
      LAYER met2 ;
        RECT 1307.410 2496.000 1307.690 2500.000 ;
    END
  END class_scores_la[8]
  PIN class_scores_la[90]
    DIRECTION OUTPUT ;
    USE SIGNAL ;
    ANTENNADIFFAREA 0.340600 ;
    PORT
      LAYER met2 ;
        RECT 1639.070 2496.000 1639.350 2500.000 ;
    END
  END class_scores_la[90]
  PIN class_scores_la[91]
    DIRECTION OUTPUT ;
    USE SIGNAL ;
    ANTENNADIFFAREA 0.340600 ;
    PORT
      LAYER met2 ;
        RECT 1561.790 2496.000 1562.070 2500.000 ;
    END
  END class_scores_la[91]
  PIN class_scores_la[92]
    DIRECTION OUTPUT ;
    USE SIGNAL ;
    ANTENNADIFFAREA 0.340600 ;
    PORT
      LAYER met2 ;
        RECT 1642.290 2496.000 1642.570 2500.000 ;
    END
  END class_scores_la[92]
  PIN class_scores_la[93]
    DIRECTION OUTPUT ;
    USE SIGNAL ;
    ANTENNADIFFAREA 0.340600 ;
    PORT
      LAYER met2 ;
        RECT 1655.170 2496.000 1655.450 2500.000 ;
    END
  END class_scores_la[93]
  PIN class_scores_la[94]
    DIRECTION OUTPUT ;
    USE SIGNAL ;
    ANTENNADIFFAREA 0.340600 ;
    PORT
      LAYER met2 ;
        RECT 1645.510 2496.000 1645.790 2500.000 ;
    END
  END class_scores_la[94]
  PIN class_scores_la[95]
    DIRECTION OUTPUT ;
    USE SIGNAL ;
    ANTENNADIFFAREA 0.340600 ;
    PORT
      LAYER met2 ;
        RECT 1565.010 2496.000 1565.290 2500.000 ;
    END
  END class_scores_la[95]
  PIN class_scores_la[96]
    DIRECTION OUTPUT ;
    USE SIGNAL ;
    ANTENNADIFFAREA 0.340600 ;
    PORT
      LAYER met2 ;
        RECT 1709.910 2496.000 1710.190 2500.000 ;
    END
  END class_scores_la[96]
  PIN class_scores_la[97]
    DIRECTION OUTPUT ;
    USE SIGNAL ;
    ANTENNADIFFAREA 0.340600 ;
    PORT
      LAYER met2 ;
        RECT 1800.070 2496.000 1800.350 2500.000 ;
    END
  END class_scores_la[97]
  PIN class_scores_la[98]
    DIRECTION OUTPUT ;
    USE SIGNAL ;
    ANTENNADIFFAREA 0.340600 ;
    PORT
      LAYER met2 ;
        RECT 1278.430 2496.000 1278.710 2500.000 ;
    END
  END class_scores_la[98]
  PIN class_scores_la[99]
    DIRECTION OUTPUT ;
    USE SIGNAL ;
    ANTENNADIFFAREA 0.340600 ;
    PORT
      LAYER met2 ;
        RECT 1629.410 2496.000 1629.690 2500.000 ;
    END
  END class_scores_la[99]
  PIN class_scores_la[9]
    DIRECTION OUTPUT ;
    USE SIGNAL ;
    ANTENNADIFFAREA 0.340600 ;
    PORT
      LAYER met2 ;
        RECT 1793.630 2496.000 1793.910 2500.000 ;
    END
  END class_scores_la[9]
  PIN clk
    DIRECTION INPUT ;
    USE SIGNAL ;
    ANTENNAGATEAREA 1.286700 ;
    ANTENNADIFFAREA 0.434700 ;
    PORT
      LAYER met3 ;
        RECT 2496.000 680.040 2500.000 680.640 ;
    END
  END clk
  PIN done
    DIRECTION OUTPUT ;
    USE SIGNAL ;
    ANTENNADIFFAREA 0.340600 ;
    PORT
      LAYER met2 ;
        RECT 1391.130 2496.000 1391.410 2500.000 ;
    END
  END done
  PIN error
    DIRECTION OUTPUT ;
    USE SIGNAL ;
    ANTENNADIFFAREA 0.340600 ;
    PORT
      LAYER met2 ;
        RECT 1381.470 2496.000 1381.750 2500.000 ;
    END
  END error
  PIN error_code[0]
    DIRECTION OUTPUT ;
    USE SIGNAL ;
    ANTENNADIFFAREA 0.340600 ;
    PORT
      LAYER met2 ;
        RECT 1329.950 2496.000 1330.230 2500.000 ;
    END
  END error_code[0]
  PIN error_code[1]
    DIRECTION OUTPUT ;
    USE SIGNAL ;
    ANTENNADIFFAREA 0.340600 ;
    PORT
      LAYER met2 ;
        RECT 1362.150 2496.000 1362.430 2500.000 ;
    END
  END error_code[1]
  PIN error_code[2]
    DIRECTION OUTPUT ;
    USE SIGNAL ;
    ANTENNADIFFAREA 0.340600 ;
    PORT
      LAYER met2 ;
        RECT 1358.930 2496.000 1359.210 2500.000 ;
    END
  END error_code[2]
  PIN error_code[3]
    DIRECTION OUTPUT ;
    USE SIGNAL ;
    ANTENNADIFFAREA 0.340600 ;
    PORT
      LAYER met2 ;
        RECT 1375.030 2496.000 1375.310 2500.000 ;
    END
  END error_code[3]
  PIN gamma_reg[0]
    DIRECTION OUTPUT ;
    USE SIGNAL ;
    ANTENNADIFFAREA 0.340600 ;
    PORT
      LAYER met2 ;
        RECT 1751.770 2496.000 1752.050 2500.000 ;
    END
  END gamma_reg[0]
  PIN gamma_reg[10]
    DIRECTION OUTPUT ;
    USE SIGNAL ;
    ANTENNADIFFAREA 0.340600 ;
    PORT
      LAYER met2 ;
        RECT 1697.030 2496.000 1697.310 2500.000 ;
    END
  END gamma_reg[10]
  PIN gamma_reg[11]
    DIRECTION OUTPUT ;
    USE SIGNAL ;
    ANTENNADIFFAREA 0.340600 ;
    PORT
      LAYER met2 ;
        RECT 1677.710 2496.000 1677.990 2500.000 ;
    END
  END gamma_reg[11]
  PIN gamma_reg[12]
    DIRECTION OUTPUT ;
    USE SIGNAL ;
    ANTENNADIFFAREA 0.340600 ;
    PORT
      LAYER met2 ;
        RECT 1735.670 2496.000 1735.950 2500.000 ;
    END
  END gamma_reg[12]
  PIN gamma_reg[13]
    DIRECTION OUTPUT ;
    USE SIGNAL ;
    ANTENNADIFFAREA 0.340600 ;
    PORT
      LAYER met2 ;
        RECT 1606.870 2496.000 1607.150 2500.000 ;
    END
  END gamma_reg[13]
  PIN gamma_reg[14]
    DIRECTION OUTPUT ;
    USE SIGNAL ;
    ANTENNADIFFAREA 0.340600 ;
    PORT
      LAYER met2 ;
        RECT 1719.570 2496.000 1719.850 2500.000 ;
    END
  END gamma_reg[14]
  PIN gamma_reg[15]
    DIRECTION OUTPUT ;
    USE SIGNAL ;
    ANTENNADIFFAREA 0.340600 ;
    PORT
      LAYER met2 ;
        RECT 1619.750 2496.000 1620.030 2500.000 ;
    END
  END gamma_reg[15]
  PIN gamma_reg[1]
    DIRECTION OUTPUT ;
    USE SIGNAL ;
    ANTENNADIFFAREA 0.340600 ;
    PORT
      LAYER met2 ;
        RECT 1758.210 2496.000 1758.490 2500.000 ;
    END
  END gamma_reg[1]
  PIN gamma_reg[2]
    DIRECTION OUTPUT ;
    USE SIGNAL ;
    ANTENNADIFFAREA 0.340600 ;
    PORT
      LAYER met2 ;
        RECT 1693.810 2496.000 1694.090 2500.000 ;
    END
  END gamma_reg[2]
  PIN gamma_reg[3]
    DIRECTION OUTPUT ;
    USE SIGNAL ;
    ANTENNADIFFAREA 0.340600 ;
    PORT
      LAYER met2 ;
        RECT 1597.210 2496.000 1597.490 2500.000 ;
    END
  END gamma_reg[3]
  PIN gamma_reg[4]
    DIRECTION OUTPUT ;
    USE SIGNAL ;
    ANTENNADIFFAREA 0.340600 ;
    PORT
      LAYER met2 ;
        RECT 1777.530 2496.000 1777.810 2500.000 ;
    END
  END gamma_reg[4]
  PIN gamma_reg[5]
    DIRECTION OUTPUT ;
    USE SIGNAL ;
    ANTENNADIFFAREA 0.340600 ;
    PORT
      LAYER met2 ;
        RECT 1690.590 2496.000 1690.870 2500.000 ;
    END
  END gamma_reg[5]
  PIN gamma_reg[6]
    DIRECTION OUTPUT ;
    USE SIGNAL ;
    ANTENNADIFFAREA 0.340600 ;
    PORT
      LAYER met2 ;
        RECT 1610.090 2496.000 1610.370 2500.000 ;
    END
  END gamma_reg[6]
  PIN gamma_reg[7]
    DIRECTION OUTPUT ;
    USE SIGNAL ;
    ANTENNADIFFAREA 0.340600 ;
    PORT
      LAYER met2 ;
        RECT 1651.950 2496.000 1652.230 2500.000 ;
    END
  END gamma_reg[7]
  PIN gamma_reg[8]
    DIRECTION OUTPUT ;
    USE SIGNAL ;
    ANTENNADIFFAREA 0.340600 ;
    PORT
      LAYER met2 ;
        RECT 1732.450 2496.000 1732.730 2500.000 ;
    END
  END gamma_reg[8]
  PIN gamma_reg[9]
    DIRECTION OUTPUT ;
    USE SIGNAL ;
    ANTENNADIFFAREA 0.340600 ;
    PORT
      LAYER met2 ;
        RECT 1600.430 2496.000 1600.710 2500.000 ;
    END
  END gamma_reg[9]
  PIN kernel_out[0]
    DIRECTION OUTPUT ;
    USE SIGNAL ;
    ANTENNADIFFAREA 0.340600 ;
    PORT
      LAYER met2 ;
        RECT 1243.010 2496.000 1243.290 2500.000 ;
    END
  END kernel_out[0]
  PIN kernel_out[10]
    DIRECTION OUTPUT ;
    USE SIGNAL ;
    ANTENNADIFFAREA 0.340600 ;
    PORT
      LAYER met2 ;
        RECT 1252.670 2496.000 1252.950 2500.000 ;
    END
  END kernel_out[10]
  PIN kernel_out[11]
    DIRECTION OUTPUT ;
    USE SIGNAL ;
    ANTENNADIFFAREA 0.340600 ;
    PORT
      LAYER met2 ;
        RECT 1249.450 2496.000 1249.730 2500.000 ;
    END
  END kernel_out[11]
  PIN kernel_out[12]
    DIRECTION OUTPUT ;
    USE SIGNAL ;
    ANTENNADIFFAREA 0.340600 ;
    PORT
      LAYER met2 ;
        RECT 1255.890 2496.000 1256.170 2500.000 ;
    END
  END kernel_out[12]
  PIN kernel_out[13]
    DIRECTION OUTPUT ;
    USE SIGNAL ;
    ANTENNADIFFAREA 0.340600 ;
    PORT
      LAYER met2 ;
        RECT 1265.550 2496.000 1265.830 2500.000 ;
    END
  END kernel_out[13]
  PIN kernel_out[14]
    DIRECTION OUTPUT ;
    USE SIGNAL ;
    ANTENNADIFFAREA 0.340600 ;
    PORT
      LAYER met2 ;
        RECT 1268.770 2496.000 1269.050 2500.000 ;
    END
  END kernel_out[14]
  PIN kernel_out[15]
    DIRECTION OUTPUT ;
    USE SIGNAL ;
    ANTENNADIFFAREA 0.340600 ;
    PORT
      LAYER met2 ;
        RECT 1262.330 2496.000 1262.610 2500.000 ;
    END
  END kernel_out[15]
  PIN kernel_out[1]
    DIRECTION OUTPUT ;
    USE SIGNAL ;
    ANTENNADIFFAREA 0.340600 ;
    PORT
      LAYER met2 ;
        RECT 1230.130 2496.000 1230.410 2500.000 ;
    END
  END kernel_out[1]
  PIN kernel_out[2]
    DIRECTION OUTPUT ;
    USE SIGNAL ;
    ANTENNADIFFAREA 0.340600 ;
    PORT
      LAYER met2 ;
        RECT 1226.910 2496.000 1227.190 2500.000 ;
    END
  END kernel_out[2]
  PIN kernel_out[3]
    DIRECTION OUTPUT ;
    USE SIGNAL ;
    ANTENNADIFFAREA 0.340600 ;
    PORT
      LAYER met2 ;
        RECT 1220.470 2496.000 1220.750 2500.000 ;
    END
  END kernel_out[3]
  PIN kernel_out[4]
    DIRECTION OUTPUT ;
    USE SIGNAL ;
    ANTENNADIFFAREA 0.340600 ;
    PORT
      LAYER met2 ;
        RECT 1223.690 2496.000 1223.970 2500.000 ;
    END
  END kernel_out[4]
  PIN kernel_out[5]
    DIRECTION OUTPUT ;
    USE SIGNAL ;
    ANTENNADIFFAREA 0.340600 ;
    PORT
      LAYER met2 ;
        RECT 1214.030 2496.000 1214.310 2500.000 ;
    END
  END kernel_out[5]
  PIN kernel_out[6]
    DIRECTION OUTPUT ;
    USE SIGNAL ;
    ANTENNADIFFAREA 0.340600 ;
    PORT
      LAYER met2 ;
        RECT 1233.350 2496.000 1233.630 2500.000 ;
    END
  END kernel_out[6]
  PIN kernel_out[7]
    DIRECTION OUTPUT ;
    USE SIGNAL ;
    ANTENNADIFFAREA 0.340600 ;
    PORT
      LAYER met2 ;
        RECT 1236.570 2496.000 1236.850 2500.000 ;
    END
  END kernel_out[7]
  PIN kernel_out[8]
    DIRECTION OUTPUT ;
    USE SIGNAL ;
    ANTENNADIFFAREA 0.340600 ;
    PORT
      LAYER met2 ;
        RECT 1217.250 2496.000 1217.530 2500.000 ;
    END
  END kernel_out[8]
  PIN kernel_out[9]
    DIRECTION OUTPUT ;
    USE SIGNAL ;
    ANTENNADIFFAREA 0.340600 ;
    PORT
      LAYER met2 ;
        RECT 1239.790 2496.000 1240.070 2500.000 ;
    END
  END kernel_out[9]
  PIN kernel_ready
    DIRECTION INPUT ;
    USE SIGNAL ;
    ANTENNAGATEAREA 0.495000 ;
    PORT
      LAYER met2 ;
        RECT 1320.290 2496.000 1320.570 2500.000 ;
    END
  END kernel_ready
  PIN kernel_valid
    DIRECTION OUTPUT ;
    USE SIGNAL ;
    ANTENNADIFFAREA 0.340600 ;
    PORT
      LAYER met2 ;
        RECT 1297.750 2496.000 1298.030 2500.000 ;
    END
  END kernel_valid
  PIN num_samples[0]
    DIRECTION INPUT ;
    USE SIGNAL ;
    ANTENNAGATEAREA 0.990000 ;
    PORT
      LAYER met2 ;
        RECT 1288.090 2496.000 1288.370 2500.000 ;
    END
  END num_samples[0]
  PIN num_samples[1]
    DIRECTION INPUT ;
    USE SIGNAL ;
    ANTENNAGATEAREA 0.990000 ;
    PORT
      LAYER met2 ;
        RECT 1281.650 2496.000 1281.930 2500.000 ;
    END
  END num_samples[1]
  PIN num_samples[2]
    DIRECTION INPUT ;
    USE SIGNAL ;
    ANTENNAGATEAREA 0.990000 ;
    PORT
      LAYER met2 ;
        RECT 1271.990 2496.000 1272.270 2500.000 ;
    END
  END num_samples[2]
  PIN num_samples[3]
    DIRECTION INPUT ;
    USE SIGNAL ;
    ANTENNAGATEAREA 0.990000 ;
    PORT
      LAYER met2 ;
        RECT 1275.210 2496.000 1275.490 2500.000 ;
    END
  END num_samples[3]
  PIN num_samples[4]
    DIRECTION INPUT ;
    USE SIGNAL ;
    ANTENNAGATEAREA 0.159000 ;
    PORT
      LAYER met3 ;
        RECT 0.000 1353.240 4.000 1353.840 ;
    END
  END num_samples[4]
  PIN num_samples[5]
    DIRECTION INPUT ;
    USE SIGNAL ;
    ANTENNAGATEAREA 0.159000 ;
    PORT
      LAYER met3 ;
        RECT 0.000 1363.440 4.000 1364.040 ;
    END
  END num_samples[5]
  PIN num_samples[6]
    DIRECTION INPUT ;
    USE SIGNAL ;
    ANTENNAGATEAREA 0.213000 ;
    PORT
      LAYER met3 ;
        RECT 0.000 1349.840 4.000 1350.440 ;
    END
  END num_samples[6]
  PIN num_samples[7]
    DIRECTION INPUT ;
    USE SIGNAL ;
    ANTENNAGATEAREA 0.213000 ;
    PORT
      LAYER met3 ;
        RECT 0.000 1370.240 4.000 1370.840 ;
    END
  END num_samples[7]
  PIN num_samples[8]
    DIRECTION INPUT ;
    USE SIGNAL ;
    ANTENNAGATEAREA 0.213000 ;
    PORT
      LAYER met3 ;
        RECT 0.000 1366.840 4.000 1367.440 ;
    END
  END num_samples[8]
  PIN num_samples[9]
    DIRECTION INPUT ;
    USE SIGNAL ;
    ANTENNAGATEAREA 0.213000 ;
    PORT
      LAYER met3 ;
        RECT 0.000 1360.040 4.000 1360.640 ;
    END
  END num_samples[9]
  PIN num_sv_per_class_flat[0]
    DIRECTION INPUT ;
    USE SIGNAL ;
    ANTENNAGATEAREA 0.990000 ;
    PORT
      LAYER met2 ;
        RECT 1349.270 2496.000 1349.550 2500.000 ;
    END
  END num_sv_per_class_flat[0]
  PIN num_sv_per_class_flat[10]
    DIRECTION INPUT ;
    USE SIGNAL ;
    ANTENNAGATEAREA 0.990000 ;
    PORT
      LAYER met2 ;
        RECT 1313.850 2496.000 1314.130 2500.000 ;
    END
  END num_sv_per_class_flat[10]
  PIN num_sv_per_class_flat[11]
    DIRECTION INPUT ;
    USE SIGNAL ;
    ANTENNAGATEAREA 0.990000 ;
    PORT
      LAYER met2 ;
        RECT 1300.970 2496.000 1301.250 2500.000 ;
    END
  END num_sv_per_class_flat[11]
  PIN num_sv_per_class_flat[12]
    DIRECTION INPUT ;
    USE SIGNAL ;
    ANTENNAGATEAREA 0.990000 ;
    PORT
      LAYER met2 ;
        RECT 1284.870 2496.000 1285.150 2500.000 ;
    END
  END num_sv_per_class_flat[12]
  PIN num_sv_per_class_flat[13]
    DIRECTION INPUT ;
    USE SIGNAL ;
    ANTENNAGATEAREA 0.126000 ;
    PORT
      LAYER met3 ;
        RECT 0.000 1458.640 4.000 1459.240 ;
    END
  END num_sv_per_class_flat[13]
  PIN num_sv_per_class_flat[14]
    DIRECTION INPUT ;
    USE SIGNAL ;
    ANTENNAGATEAREA 0.196500 ;
    PORT
      LAYER met3 ;
        RECT 0.000 1506.240 4.000 1506.840 ;
    END
  END num_sv_per_class_flat[14]
  PIN num_sv_per_class_flat[15]
    DIRECTION INPUT ;
    USE SIGNAL ;
    ANTENNAGATEAREA 0.196500 ;
    PORT
      LAYER met3 ;
        RECT 0.000 1502.840 4.000 1503.440 ;
    END
  END num_sv_per_class_flat[15]
  PIN num_sv_per_class_flat[16]
    DIRECTION INPUT ;
    USE SIGNAL ;
    ANTENNAGATEAREA 0.990000 ;
    PORT
      LAYER met2 ;
        RECT 1346.050 2496.000 1346.330 2500.000 ;
    END
  END num_sv_per_class_flat[16]
  PIN num_sv_per_class_flat[17]
    DIRECTION INPUT ;
    USE SIGNAL ;
    ANTENNAGATEAREA 0.990000 ;
    PORT
      LAYER met2 ;
        RECT 1336.390 2496.000 1336.670 2500.000 ;
    END
  END num_sv_per_class_flat[17]
  PIN num_sv_per_class_flat[18]
    DIRECTION INPUT ;
    USE SIGNAL ;
    ANTENNAGATEAREA 0.990000 ;
    PORT
      LAYER met2 ;
        RECT 1326.730 2496.000 1327.010 2500.000 ;
    END
  END num_sv_per_class_flat[18]
  PIN num_sv_per_class_flat[19]
    DIRECTION INPUT ;
    USE SIGNAL ;
    ANTENNAGATEAREA 0.990000 ;
    PORT
      LAYER met2 ;
        RECT 1304.190 2496.000 1304.470 2500.000 ;
    END
  END num_sv_per_class_flat[19]
  PIN num_sv_per_class_flat[1]
    DIRECTION INPUT ;
    USE SIGNAL ;
    ANTENNAGATEAREA 0.990000 ;
    PORT
      LAYER met2 ;
        RECT 1342.830 2496.000 1343.110 2500.000 ;
    END
  END num_sv_per_class_flat[1]
  PIN num_sv_per_class_flat[20]
    DIRECTION INPUT ;
    USE SIGNAL ;
    ANTENNAGATEAREA 0.213000 ;
    PORT
      LAYER met3 ;
        RECT 0.000 1438.240 4.000 1438.840 ;
    END
  END num_sv_per_class_flat[20]
  PIN num_sv_per_class_flat[21]
    DIRECTION INPUT ;
    USE SIGNAL ;
    ANTENNAGATEAREA 0.213000 ;
    PORT
      LAYER met3 ;
        RECT 0.000 1445.040 4.000 1445.640 ;
    END
  END num_sv_per_class_flat[21]
  PIN num_sv_per_class_flat[22]
    DIRECTION INPUT ;
    USE SIGNAL ;
    ANTENNAGATEAREA 0.126000 ;
    PORT
      LAYER met3 ;
        RECT 0.000 1482.440 4.000 1483.040 ;
    END
  END num_sv_per_class_flat[22]
  PIN num_sv_per_class_flat[23]
    DIRECTION INPUT ;
    USE SIGNAL ;
    ANTENNAGATEAREA 0.126000 ;
    PORT
      LAYER met3 ;
        RECT 0.000 1475.640 4.000 1476.240 ;
    END
  END num_sv_per_class_flat[23]
  PIN num_sv_per_class_flat[24]
    DIRECTION INPUT ;
    USE SIGNAL ;
    ANTENNAGATEAREA 0.159000 ;
    PORT
      LAYER met3 ;
        RECT 0.000 1346.440 4.000 1347.040 ;
    END
  END num_sv_per_class_flat[24]
  PIN num_sv_per_class_flat[25]
    DIRECTION INPUT ;
    USE SIGNAL ;
    ANTENNAGATEAREA 0.213000 ;
    PORT
      LAYER met3 ;
        RECT 0.000 1417.840 4.000 1418.440 ;
    END
  END num_sv_per_class_flat[25]
  PIN num_sv_per_class_flat[26]
    DIRECTION INPUT ;
    USE SIGNAL ;
    ANTENNAGATEAREA 0.213000 ;
    PORT
      LAYER met3 ;
        RECT 0.000 1421.240 4.000 1421.840 ;
    END
  END num_sv_per_class_flat[26]
  PIN num_sv_per_class_flat[27]
    DIRECTION INPUT ;
    USE SIGNAL ;
    ANTENNAGATEAREA 0.213000 ;
    PORT
      LAYER met3 ;
        RECT 0.000 1424.640 4.000 1425.240 ;
    END
  END num_sv_per_class_flat[27]
  PIN num_sv_per_class_flat[28]
    DIRECTION INPUT ;
    USE SIGNAL ;
    ANTENNAGATEAREA 0.213000 ;
    PORT
      LAYER met3 ;
        RECT 0.000 1434.840 4.000 1435.440 ;
    END
  END num_sv_per_class_flat[28]
  PIN num_sv_per_class_flat[29]
    DIRECTION INPUT ;
    USE SIGNAL ;
    ANTENNAGATEAREA 0.213000 ;
    PORT
      LAYER met3 ;
        RECT 0.000 1428.040 4.000 1428.640 ;
    END
  END num_sv_per_class_flat[29]
  PIN num_sv_per_class_flat[2]
    DIRECTION INPUT ;
    USE SIGNAL ;
    ANTENNAGATEAREA 0.213000 ;
    PORT
      LAYER met3 ;
        RECT 0.000 1465.440 4.000 1466.040 ;
    END
  END num_sv_per_class_flat[2]
  PIN num_sv_per_class_flat[30]
    DIRECTION INPUT ;
    USE SIGNAL ;
    ANTENNAGATEAREA 0.196500 ;
    PORT
      LAYER met3 ;
        RECT 0.000 1479.040 4.000 1479.640 ;
    END
  END num_sv_per_class_flat[30]
  PIN num_sv_per_class_flat[31]
    DIRECTION INPUT ;
    USE SIGNAL ;
    ANTENNAGATEAREA 0.196500 ;
    PORT
      LAYER met3 ;
        RECT 0.000 1492.640 4.000 1493.240 ;
    END
  END num_sv_per_class_flat[31]
  PIN num_sv_per_class_flat[32]
    DIRECTION INPUT ;
    USE SIGNAL ;
    ANTENNAGATEAREA 0.213000 ;
    PORT
      LAYER met3 ;
        RECT 0.000 1380.440 4.000 1381.040 ;
    END
  END num_sv_per_class_flat[32]
  PIN num_sv_per_class_flat[33]
    DIRECTION INPUT ;
    USE SIGNAL ;
    ANTENNAGATEAREA 0.213000 ;
    PORT
      LAYER met3 ;
        RECT 0.000 1339.640 4.000 1340.240 ;
    END
  END num_sv_per_class_flat[33]
  PIN num_sv_per_class_flat[34]
    DIRECTION INPUT ;
    USE SIGNAL ;
    ANTENNAGATEAREA 0.213000 ;
    PORT
      LAYER met3 ;
        RECT 0.000 1397.440 4.000 1398.040 ;
    END
  END num_sv_per_class_flat[34]
  PIN num_sv_per_class_flat[35]
    DIRECTION INPUT ;
    USE SIGNAL ;
    ANTENNAGATEAREA 0.213000 ;
    PORT
      LAYER met3 ;
        RECT 0.000 1390.640 4.000 1391.240 ;
    END
  END num_sv_per_class_flat[35]
  PIN num_sv_per_class_flat[36]
    DIRECTION INPUT ;
    USE SIGNAL ;
    ANTENNAGATEAREA 0.126000 ;
    PORT
      LAYER met3 ;
        RECT 0.000 1431.440 4.000 1432.040 ;
    END
  END num_sv_per_class_flat[36]
  PIN num_sv_per_class_flat[37]
    DIRECTION INPUT ;
    USE SIGNAL ;
    ANTENNAGATEAREA 0.196500 ;
    PORT
      LAYER met3 ;
        RECT 0.000 1448.440 4.000 1449.040 ;
    END
  END num_sv_per_class_flat[37]
  PIN num_sv_per_class_flat[38]
    DIRECTION INPUT ;
    USE SIGNAL ;
    ANTENNAGATEAREA 0.196500 ;
    PORT
      LAYER met3 ;
        RECT 0.000 1499.440 4.000 1500.040 ;
    END
  END num_sv_per_class_flat[38]
  PIN num_sv_per_class_flat[39]
    DIRECTION INPUT ;
    USE SIGNAL ;
    ANTENNAGATEAREA 0.196500 ;
    PORT
      LAYER met3 ;
        RECT 0.000 1496.040 4.000 1496.640 ;
    END
  END num_sv_per_class_flat[39]
  PIN num_sv_per_class_flat[3]
    DIRECTION INPUT ;
    USE SIGNAL ;
    ANTENNAGATEAREA 0.213000 ;
    PORT
      LAYER met3 ;
        RECT 0.000 1455.240 4.000 1455.840 ;
    END
  END num_sv_per_class_flat[3]
  PIN num_sv_per_class_flat[4]
    DIRECTION INPUT ;
    USE SIGNAL ;
    ANTENNAGATEAREA 0.213000 ;
    PORT
      LAYER met3 ;
        RECT 0.000 1441.640 4.000 1442.240 ;
    END
  END num_sv_per_class_flat[4]
  PIN num_sv_per_class_flat[5]
    DIRECTION INPUT ;
    USE SIGNAL ;
    ANTENNAGATEAREA 0.126000 ;
    PORT
      LAYER met3 ;
        RECT 0.000 1462.040 4.000 1462.640 ;
    END
  END num_sv_per_class_flat[5]
  PIN num_sv_per_class_flat[6]
    DIRECTION INPUT ;
    USE SIGNAL ;
    ANTENNAGATEAREA 0.196500 ;
    PORT
      LAYER met3 ;
        RECT 0.000 1485.840 4.000 1486.440 ;
    END
  END num_sv_per_class_flat[6]
  PIN num_sv_per_class_flat[7]
    DIRECTION INPUT ;
    USE SIGNAL ;
    ANTENNAGATEAREA 0.196500 ;
    PORT
      LAYER met3 ;
        RECT 0.000 1489.240 4.000 1489.840 ;
    END
  END num_sv_per_class_flat[7]
  PIN num_sv_per_class_flat[8]
    DIRECTION INPUT ;
    USE SIGNAL ;
    ANTENNAGATEAREA 0.159000 ;
    PORT
      LAYER met3 ;
        RECT 0.000 1394.040 4.000 1394.640 ;
    END
  END num_sv_per_class_flat[8]
  PIN num_sv_per_class_flat[9]
    DIRECTION INPUT ;
    USE SIGNAL ;
    ANTENNAGATEAREA 0.990000 ;
    PORT
      LAYER met3 ;
        RECT 2496.000 1428.040 2500.000 1428.640 ;
    END
  END num_sv_per_class_flat[9]
  PIN param_addr[0]
    DIRECTION INPUT ;
    USE SIGNAL ;
    ANTENNAGATEAREA 0.990000 ;
    PORT
      LAYER met3 ;
        RECT 2496.000 1608.240 2500.000 1608.840 ;
    END
  END param_addr[0]
  PIN param_addr[1]
    DIRECTION INPUT ;
    USE SIGNAL ;
    ANTENNAGATEAREA 0.990000 ;
    PORT
      LAYER met3 ;
        RECT 2496.000 1615.040 2500.000 1615.640 ;
    END
  END param_addr[1]
  PIN param_addr[2]
    DIRECTION INPUT ;
    USE SIGNAL ;
    ANTENNAGATEAREA 0.990000 ;
    PORT
      LAYER met3 ;
        RECT 2496.000 1618.440 2500.000 1619.040 ;
    END
  END param_addr[2]
  PIN param_data[0]
    DIRECTION INPUT ;
    USE SIGNAL ;
    ANTENNAGATEAREA 0.990000 ;
    PORT
      LAYER met3 ;
        RECT 2496.000 1536.840 2500.000 1537.440 ;
    END
  END param_data[0]
  PIN param_data[10]
    DIRECTION INPUT ;
    USE SIGNAL ;
    ANTENNAGATEAREA 0.990000 ;
    PORT
      LAYER met3 ;
        RECT 2496.000 1564.040 2500.000 1564.640 ;
    END
  END param_data[10]
  PIN param_data[11]
    DIRECTION INPUT ;
    USE SIGNAL ;
    ANTENNAGATEAREA 0.990000 ;
    PORT
      LAYER met3 ;
        RECT 2496.000 1601.440 2500.000 1602.040 ;
    END
  END param_data[11]
  PIN param_data[12]
    DIRECTION INPUT ;
    USE SIGNAL ;
    ANTENNAGATEAREA 0.990000 ;
    PORT
      LAYER met3 ;
        RECT 2496.000 1540.240 2500.000 1540.840 ;
    END
  END param_data[12]
  PIN param_data[13]
    DIRECTION INPUT ;
    USE SIGNAL ;
    ANTENNAGATEAREA 0.990000 ;
    PORT
      LAYER met3 ;
        RECT 2496.000 1533.440 2500.000 1534.040 ;
    END
  END param_data[13]
  PIN param_data[14]
    DIRECTION INPUT ;
    USE SIGNAL ;
    ANTENNAGATEAREA 0.990000 ;
    PORT
      LAYER met3 ;
        RECT 2496.000 1543.640 2500.000 1544.240 ;
    END
  END param_data[14]
  PIN param_data[15]
    DIRECTION INPUT ;
    USE SIGNAL ;
    ANTENNAGATEAREA 0.990000 ;
    PORT
      LAYER met3 ;
        RECT 2496.000 1547.040 2500.000 1547.640 ;
    END
  END param_data[15]
  PIN param_data[1]
    DIRECTION INPUT ;
    USE SIGNAL ;
    ANTENNAGATEAREA 0.990000 ;
    PORT
      LAYER met3 ;
        RECT 2496.000 1574.240 2500.000 1574.840 ;
    END
  END param_data[1]
  PIN param_data[2]
    DIRECTION INPUT ;
    USE SIGNAL ;
    ANTENNAGATEAREA 0.990000 ;
    PORT
      LAYER met3 ;
        RECT 2496.000 1570.840 2500.000 1571.440 ;
    END
  END param_data[2]
  PIN param_data[3]
    DIRECTION INPUT ;
    USE SIGNAL ;
    ANTENNAGATEAREA 0.990000 ;
    PORT
      LAYER met3 ;
        RECT 2496.000 1550.440 2500.000 1551.040 ;
    END
  END param_data[3]
  PIN param_data[4]
    DIRECTION INPUT ;
    USE SIGNAL ;
    ANTENNAGATEAREA 0.990000 ;
    PORT
      LAYER met3 ;
        RECT 2496.000 1557.240 2500.000 1557.840 ;
    END
  END param_data[4]
  PIN param_data[5]
    DIRECTION INPUT ;
    USE SIGNAL ;
    ANTENNAGATEAREA 0.990000 ;
    PORT
      LAYER met3 ;
        RECT 2496.000 1584.440 2500.000 1585.040 ;
    END
  END param_data[5]
  PIN param_data[6]
    DIRECTION INPUT ;
    USE SIGNAL ;
    ANTENNAGATEAREA 0.990000 ;
    PORT
      LAYER met3 ;
        RECT 2496.000 1553.840 2500.000 1554.440 ;
    END
  END param_data[6]
  PIN param_data[7]
    DIRECTION INPUT ;
    USE SIGNAL ;
    ANTENNAGATEAREA 0.990000 ;
    PORT
      LAYER met3 ;
        RECT 2496.000 1604.840 2500.000 1605.440 ;
    END
  END param_data[7]
  PIN param_data[8]
    DIRECTION INPUT ;
    USE SIGNAL ;
    ANTENNAGATEAREA 0.990000 ;
    PORT
      LAYER met3 ;
        RECT 2496.000 1591.240 2500.000 1591.840 ;
    END
  END param_data[8]
  PIN param_data[9]
    DIRECTION INPUT ;
    USE SIGNAL ;
    ANTENNAGATEAREA 0.990000 ;
    PORT
      LAYER met3 ;
        RECT 2496.000 1587.840 2500.000 1588.440 ;
    END
  END param_data[9]
  PIN param_write_en
    DIRECTION INPUT ;
    USE SIGNAL ;
    ANTENNAGATEAREA 0.990000 ;
    PORT
      LAYER met3 ;
        RECT 2496.000 1611.640 2500.000 1612.240 ;
    END
  END param_write_en
  PIN ram_addr[0]
    DIRECTION OUTPUT ;
    USE SIGNAL ;
    ANTENNADIFFAREA 0.340600 ;
    PORT
      LAYER met3 ;
        RECT 2496.000 979.240 2500.000 979.840 ;
    END
  END ram_addr[0]
  PIN ram_addr[10]
    DIRECTION OUTPUT ;
    USE SIGNAL ;
    ANTENNADIFFAREA 0.340600 ;
    PORT
      LAYER met3 ;
        RECT 0.000 1404.240 4.000 1404.840 ;
    END
  END ram_addr[10]
  PIN ram_addr[11]
    DIRECTION OUTPUT ;
    USE SIGNAL ;
    ANTENNADIFFAREA 0.340600 ;
    PORT
      LAYER met3 ;
        RECT 0.000 1400.840 4.000 1401.440 ;
    END
  END ram_addr[11]
  PIN ram_addr[12]
    DIRECTION OUTPUT ;
    USE SIGNAL ;
    ANTENNADIFFAREA 0.340600 ;
    PORT
      LAYER met3 ;
        RECT 0.000 1373.640 4.000 1374.240 ;
    END
  END ram_addr[12]
  PIN ram_addr[13]
    DIRECTION OUTPUT ;
    USE SIGNAL ;
    ANTENNADIFFAREA 0.340600 ;
    PORT
      LAYER met3 ;
        RECT 0.000 1377.040 4.000 1377.640 ;
    END
  END ram_addr[13]
  PIN ram_addr[14]
    DIRECTION OUTPUT ;
    USE SIGNAL ;
    ANTENNADIFFAREA 0.340600 ;
    PORT
      LAYER met3 ;
        RECT 0.000 1407.640 4.000 1408.240 ;
    END
  END ram_addr[14]
  PIN ram_addr[15]
    DIRECTION OUTPUT ;
    USE SIGNAL ;
    ANTENNADIFFAREA 0.340600 ;
    PORT
      LAYER met3 ;
        RECT 0.000 1468.840 4.000 1469.440 ;
    END
  END ram_addr[15]
  PIN ram_addr[16]
    DIRECTION OUTPUT ;
    USE SIGNAL ;
    ANTENNADIFFAREA 0.340600 ;
    PORT
      LAYER met3 ;
        RECT 0.000 1451.840 4.000 1452.440 ;
    END
  END ram_addr[16]
  PIN ram_addr[17]
    DIRECTION OUTPUT ;
    USE SIGNAL ;
    ANTENNADIFFAREA 0.340600 ;
    PORT
      LAYER met3 ;
        RECT 0.000 1411.040 4.000 1411.640 ;
    END
  END ram_addr[17]
  PIN ram_addr[18]
    DIRECTION OUTPUT ;
    USE SIGNAL ;
    ANTENNADIFFAREA 0.340600 ;
    PORT
      LAYER met3 ;
        RECT 0.000 1343.040 4.000 1343.640 ;
    END
  END ram_addr[18]
  PIN ram_addr[1]
    DIRECTION OUTPUT ;
    USE SIGNAL ;
    ANTENNADIFFAREA 0.340600 ;
    PORT
      LAYER met3 ;
        RECT 2496.000 989.440 2500.000 990.040 ;
    END
  END ram_addr[1]
  PIN ram_addr[2]
    DIRECTION OUTPUT ;
    USE SIGNAL ;
    ANTENNADIFFAREA 0.340600 ;
    PORT
      LAYER met3 ;
        RECT 2496.000 992.840 2500.000 993.440 ;
    END
  END ram_addr[2]
  PIN ram_addr[3]
    DIRECTION OUTPUT ;
    USE SIGNAL ;
    ANTENNADIFFAREA 0.340600 ;
    PORT
      LAYER met3 ;
        RECT 2496.000 999.640 2500.000 1000.240 ;
    END
  END ram_addr[3]
  PIN ram_addr[4]
    DIRECTION OUTPUT ;
    USE SIGNAL ;
    ANTENNADIFFAREA 0.340600 ;
    PORT
      LAYER met3 ;
        RECT 2496.000 958.840 2500.000 959.440 ;
    END
  END ram_addr[4]
  PIN ram_addr[5]
    DIRECTION OUTPUT ;
    USE SIGNAL ;
    ANTENNADIFFAREA 0.340600 ;
    PORT
      LAYER met3 ;
        RECT 2496.000 969.040 2500.000 969.640 ;
    END
  END ram_addr[5]
  PIN ram_addr[6]
    DIRECTION OUTPUT ;
    USE SIGNAL ;
    ANTENNADIFFAREA 0.340600 ;
    PORT
      LAYER met3 ;
        RECT 2496.000 962.240 2500.000 962.840 ;
    END
  END ram_addr[6]
  PIN ram_addr[7]
    DIRECTION OUTPUT ;
    USE SIGNAL ;
    ANTENNADIFFAREA 0.340600 ;
    PORT
      LAYER met3 ;
        RECT 2496.000 965.640 2500.000 966.240 ;
    END
  END ram_addr[7]
  PIN ram_addr[8]
    DIRECTION OUTPUT ;
    USE SIGNAL ;
    ANTENNADIFFAREA 0.340600 ;
    PORT
      LAYER met3 ;
        RECT 0.000 1387.240 4.000 1387.840 ;
    END
  END ram_addr[8]
  PIN ram_addr[9]
    DIRECTION OUTPUT ;
    USE SIGNAL ;
    ANTENNADIFFAREA 0.340600 ;
    PORT
      LAYER met3 ;
        RECT 0.000 1383.840 4.000 1384.440 ;
    END
  END ram_addr[9]
  PIN ram_rdata[0]
    DIRECTION INPUT ;
    USE SIGNAL ;
    ANTENNAGATEAREA 0.852000 ;
    PORT
      LAYER met3 ;
        RECT 2496.000 683.440 2500.000 684.040 ;
    END
  END ram_rdata[0]
  PIN ram_rdata[10]
    DIRECTION INPUT ;
    USE SIGNAL ;
    ANTENNAGATEAREA 0.990000 ;
    PORT
      LAYER met3 ;
        RECT 2496.000 686.840 2500.000 687.440 ;
    END
  END ram_rdata[10]
  PIN ram_rdata[11]
    DIRECTION INPUT ;
    USE SIGNAL ;
    ANTENNAGATEAREA 0.852000 ;
    PORT
      LAYER met3 ;
        RECT 2496.000 690.240 2500.000 690.840 ;
    END
  END ram_rdata[11]
  PIN ram_rdata[12]
    DIRECTION INPUT ;
    USE SIGNAL ;
    ANTENNAGATEAREA 0.990000 ;
    PORT
      LAYER met3 ;
        RECT 2496.000 693.640 2500.000 694.240 ;
    END
  END ram_rdata[12]
  PIN ram_rdata[13]
    DIRECTION INPUT ;
    USE SIGNAL ;
    ANTENNAGATEAREA 0.990000 ;
    PORT
      LAYER met3 ;
        RECT 2496.000 697.040 2500.000 697.640 ;
    END
  END ram_rdata[13]
  PIN ram_rdata[14]
    DIRECTION INPUT ;
    USE SIGNAL ;
    ANTENNAGATEAREA 0.990000 ;
    PORT
      LAYER met3 ;
        RECT 2496.000 700.440 2500.000 701.040 ;
    END
  END ram_rdata[14]
  PIN ram_rdata[15]
    DIRECTION INPUT ;
    USE SIGNAL ;
    ANTENNAGATEAREA 0.852000 ;
    PORT
      LAYER met3 ;
        RECT 2496.000 703.840 2500.000 704.440 ;
    END
  END ram_rdata[15]
  PIN ram_rdata[1]
    DIRECTION INPUT ;
    USE SIGNAL ;
    ANTENNAGATEAREA 0.990000 ;
    PORT
      LAYER met3 ;
        RECT 2496.000 707.240 2500.000 707.840 ;
    END
  END ram_rdata[1]
  PIN ram_rdata[2]
    DIRECTION INPUT ;
    USE SIGNAL ;
    ANTENNAGATEAREA 0.495000 ;
    PORT
      LAYER met3 ;
        RECT 2496.000 710.640 2500.000 711.240 ;
    END
  END ram_rdata[2]
  PIN ram_rdata[3]
    DIRECTION INPUT ;
    USE SIGNAL ;
    ANTENNAGATEAREA 0.852000 ;
    PORT
      LAYER met3 ;
        RECT 2496.000 714.040 2500.000 714.640 ;
    END
  END ram_rdata[3]
  PIN ram_rdata[4]
    DIRECTION INPUT ;
    USE SIGNAL ;
    ANTENNAGATEAREA 0.742500 ;
    PORT
      LAYER met3 ;
        RECT 2496.000 717.440 2500.000 718.040 ;
    END
  END ram_rdata[4]
  PIN ram_rdata[5]
    DIRECTION INPUT ;
    USE SIGNAL ;
    ANTENNAGATEAREA 0.852000 ;
    PORT
      LAYER met3 ;
        RECT 2496.000 720.840 2500.000 721.440 ;
    END
  END ram_rdata[5]
  PIN ram_rdata[6]
    DIRECTION INPUT ;
    USE SIGNAL ;
    ANTENNAGATEAREA 0.852000 ;
    PORT
      LAYER met3 ;
        RECT 2496.000 724.240 2500.000 724.840 ;
    END
  END ram_rdata[6]
  PIN ram_rdata[7]
    DIRECTION INPUT ;
    USE SIGNAL ;
    ANTENNAGATEAREA 0.426000 ;
    PORT
      LAYER met3 ;
        RECT 2496.000 727.640 2500.000 728.240 ;
    END
  END ram_rdata[7]
  PIN ram_rdata[8]
    DIRECTION INPUT ;
    USE SIGNAL ;
    ANTENNAGATEAREA 0.852000 ;
    PORT
      LAYER met3 ;
        RECT 2496.000 731.040 2500.000 731.640 ;
    END
  END ram_rdata[8]
  PIN ram_rdata[9]
    DIRECTION INPUT ;
    USE SIGNAL ;
    ANTENNAGATEAREA 0.990000 ;
    PORT
      LAYER met3 ;
        RECT 2496.000 734.440 2500.000 735.040 ;
    END
  END ram_rdata[9]
  PIN ram_ren
    DIRECTION OUTPUT ;
    USE SIGNAL ;
    ANTENNADIFFAREA 0.340600 ;
    PORT
      LAYER met3 ;
        RECT 2496.000 975.840 2500.000 976.440 ;
    END
  END ram_ren
  PIN rst_n
    DIRECTION INPUT ;
    USE SIGNAL ;
    ANTENNAGATEAREA 0.852000 ;
    PORT
      LAYER met3 ;
        RECT 0.000 1764.640 4.000 1765.240 ;
    END
  END rst_n
  PIN sample_rdy
    DIRECTION OUTPUT ;
    USE SIGNAL ;
    ANTENNADIFFAREA 0.340600 ;
    PORT
      LAYER met3 ;
        RECT 2496.000 1380.440 2500.000 1381.040 ;
    END
  END sample_rdy
  PIN start
    DIRECTION INPUT ;
    USE SIGNAL ;
    ANTENNAGATEAREA 0.742500 ;
    PORT
      LAYER met3 ;
        RECT 2496.000 1417.840 2500.000 1418.440 ;
    END
  END start
  PIN vbatt_ok
    DIRECTION INPUT ;
    USE SIGNAL ;
    ANTENNAGATEAREA 0.742500 ;
    PORT
      LAYER met3 ;
        RECT 2496.000 1390.640 2500.000 1391.240 ;
    END
  END vbatt_ok
  PIN vbatt_warn
    DIRECTION INPUT ;
    USE SIGNAL ;
    ANTENNAGATEAREA 0.495000 ;
    PORT
      LAYER met3 ;
        RECT 2496.000 1387.240 2500.000 1387.840 ;
    END
  END vbatt_warn
  OBS
      LAYER nwell ;
        RECT 5.330 10.795 2494.310 2488.990 ;
      LAYER li1 ;
        RECT 5.520 10.795 2494.120 2488.885 ;
      LAYER met1 ;
        RECT 4.210 10.640 2494.120 2491.480 ;
      LAYER met2 ;
        RECT 4.230 2495.720 875.650 2496.690 ;
        RECT 876.490 2495.720 878.870 2496.690 ;
        RECT 879.710 2495.720 882.090 2496.690 ;
        RECT 882.930 2495.720 885.310 2496.690 ;
        RECT 886.150 2495.720 888.530 2496.690 ;
        RECT 889.370 2495.720 891.750 2496.690 ;
        RECT 892.590 2495.720 1213.750 2496.690 ;
        RECT 1214.590 2495.720 1216.970 2496.690 ;
        RECT 1217.810 2495.720 1220.190 2496.690 ;
        RECT 1221.030 2495.720 1223.410 2496.690 ;
        RECT 1224.250 2495.720 1226.630 2496.690 ;
        RECT 1227.470 2495.720 1229.850 2496.690 ;
        RECT 1230.690 2495.720 1233.070 2496.690 ;
        RECT 1233.910 2495.720 1236.290 2496.690 ;
        RECT 1237.130 2495.720 1239.510 2496.690 ;
        RECT 1240.350 2495.720 1242.730 2496.690 ;
        RECT 1243.570 2495.720 1245.950 2496.690 ;
        RECT 1246.790 2495.720 1249.170 2496.690 ;
        RECT 1250.010 2495.720 1252.390 2496.690 ;
        RECT 1253.230 2495.720 1255.610 2496.690 ;
        RECT 1256.450 2495.720 1258.830 2496.690 ;
        RECT 1259.670 2495.720 1262.050 2496.690 ;
        RECT 1262.890 2495.720 1265.270 2496.690 ;
        RECT 1266.110 2495.720 1268.490 2496.690 ;
        RECT 1269.330 2495.720 1271.710 2496.690 ;
        RECT 1272.550 2495.720 1274.930 2496.690 ;
        RECT 1275.770 2495.720 1278.150 2496.690 ;
        RECT 1278.990 2495.720 1281.370 2496.690 ;
        RECT 1282.210 2495.720 1284.590 2496.690 ;
        RECT 1285.430 2495.720 1287.810 2496.690 ;
        RECT 1288.650 2495.720 1291.030 2496.690 ;
        RECT 1291.870 2495.720 1294.250 2496.690 ;
        RECT 1295.090 2495.720 1297.470 2496.690 ;
        RECT 1298.310 2495.720 1300.690 2496.690 ;
        RECT 1301.530 2495.720 1303.910 2496.690 ;
        RECT 1304.750 2495.720 1307.130 2496.690 ;
        RECT 1307.970 2495.720 1310.350 2496.690 ;
        RECT 1311.190 2495.720 1313.570 2496.690 ;
        RECT 1314.410 2495.720 1316.790 2496.690 ;
        RECT 1317.630 2495.720 1320.010 2496.690 ;
        RECT 1320.850 2495.720 1323.230 2496.690 ;
        RECT 1324.070 2495.720 1326.450 2496.690 ;
        RECT 1327.290 2495.720 1329.670 2496.690 ;
        RECT 1330.510 2495.720 1332.890 2496.690 ;
        RECT 1333.730 2495.720 1336.110 2496.690 ;
        RECT 1336.950 2495.720 1339.330 2496.690 ;
        RECT 1340.170 2495.720 1342.550 2496.690 ;
        RECT 1343.390 2495.720 1345.770 2496.690 ;
        RECT 1346.610 2495.720 1348.990 2496.690 ;
        RECT 1349.830 2495.720 1352.210 2496.690 ;
        RECT 1353.050 2495.720 1355.430 2496.690 ;
        RECT 1356.270 2495.720 1358.650 2496.690 ;
        RECT 1359.490 2495.720 1361.870 2496.690 ;
        RECT 1362.710 2495.720 1365.090 2496.690 ;
        RECT 1365.930 2495.720 1368.310 2496.690 ;
        RECT 1369.150 2495.720 1371.530 2496.690 ;
        RECT 1372.370 2495.720 1374.750 2496.690 ;
        RECT 1375.590 2495.720 1377.970 2496.690 ;
        RECT 1378.810 2495.720 1381.190 2496.690 ;
        RECT 1382.030 2495.720 1384.410 2496.690 ;
        RECT 1385.250 2495.720 1387.630 2496.690 ;
        RECT 1388.470 2495.720 1390.850 2496.690 ;
        RECT 1391.690 2495.720 1394.070 2496.690 ;
        RECT 1394.910 2495.720 1397.290 2496.690 ;
        RECT 1398.130 2495.720 1400.510 2496.690 ;
        RECT 1401.350 2495.720 1403.730 2496.690 ;
        RECT 1404.570 2495.720 1406.950 2496.690 ;
        RECT 1407.790 2495.720 1410.170 2496.690 ;
        RECT 1411.010 2495.720 1413.390 2496.690 ;
        RECT 1414.230 2495.720 1416.610 2496.690 ;
        RECT 1417.450 2495.720 1419.830 2496.690 ;
        RECT 1420.670 2495.720 1423.050 2496.690 ;
        RECT 1423.890 2495.720 1426.270 2496.690 ;
        RECT 1427.110 2495.720 1429.490 2496.690 ;
        RECT 1430.330 2495.720 1432.710 2496.690 ;
        RECT 1433.550 2495.720 1435.930 2496.690 ;
        RECT 1436.770 2495.720 1439.150 2496.690 ;
        RECT 1439.990 2495.720 1442.370 2496.690 ;
        RECT 1443.210 2495.720 1445.590 2496.690 ;
        RECT 1446.430 2495.720 1448.810 2496.690 ;
        RECT 1449.650 2495.720 1452.030 2496.690 ;
        RECT 1452.870 2495.720 1455.250 2496.690 ;
        RECT 1456.090 2495.720 1458.470 2496.690 ;
        RECT 1459.310 2495.720 1461.690 2496.690 ;
        RECT 1462.530 2495.720 1464.910 2496.690 ;
        RECT 1465.750 2495.720 1468.130 2496.690 ;
        RECT 1468.970 2495.720 1471.350 2496.690 ;
        RECT 1472.190 2495.720 1474.570 2496.690 ;
        RECT 1475.410 2495.720 1477.790 2496.690 ;
        RECT 1478.630 2495.720 1481.010 2496.690 ;
        RECT 1481.850 2495.720 1484.230 2496.690 ;
        RECT 1485.070 2495.720 1487.450 2496.690 ;
        RECT 1488.290 2495.720 1490.670 2496.690 ;
        RECT 1491.510 2495.720 1493.890 2496.690 ;
        RECT 1494.730 2495.720 1497.110 2496.690 ;
        RECT 1497.950 2495.720 1500.330 2496.690 ;
        RECT 1501.170 2495.720 1503.550 2496.690 ;
        RECT 1504.390 2495.720 1506.770 2496.690 ;
        RECT 1507.610 2495.720 1509.990 2496.690 ;
        RECT 1510.830 2495.720 1513.210 2496.690 ;
        RECT 1514.050 2495.720 1516.430 2496.690 ;
        RECT 1517.270 2495.720 1519.650 2496.690 ;
        RECT 1520.490 2495.720 1522.870 2496.690 ;
        RECT 1523.710 2495.720 1526.090 2496.690 ;
        RECT 1526.930 2495.720 1529.310 2496.690 ;
        RECT 1530.150 2495.720 1532.530 2496.690 ;
        RECT 1533.370 2495.720 1535.750 2496.690 ;
        RECT 1536.590 2495.720 1538.970 2496.690 ;
        RECT 1539.810 2495.720 1542.190 2496.690 ;
        RECT 1543.030 2495.720 1545.410 2496.690 ;
        RECT 1546.250 2495.720 1548.630 2496.690 ;
        RECT 1549.470 2495.720 1551.850 2496.690 ;
        RECT 1552.690 2495.720 1555.070 2496.690 ;
        RECT 1555.910 2495.720 1558.290 2496.690 ;
        RECT 1559.130 2495.720 1561.510 2496.690 ;
        RECT 1562.350 2495.720 1564.730 2496.690 ;
        RECT 1565.570 2495.720 1567.950 2496.690 ;
        RECT 1568.790 2495.720 1571.170 2496.690 ;
        RECT 1572.010 2495.720 1574.390 2496.690 ;
        RECT 1575.230 2495.720 1577.610 2496.690 ;
        RECT 1578.450 2495.720 1580.830 2496.690 ;
        RECT 1581.670 2495.720 1584.050 2496.690 ;
        RECT 1584.890 2495.720 1587.270 2496.690 ;
        RECT 1588.110 2495.720 1590.490 2496.690 ;
        RECT 1591.330 2495.720 1593.710 2496.690 ;
        RECT 1594.550 2495.720 1596.930 2496.690 ;
        RECT 1597.770 2495.720 1600.150 2496.690 ;
        RECT 1600.990 2495.720 1603.370 2496.690 ;
        RECT 1604.210 2495.720 1606.590 2496.690 ;
        RECT 1607.430 2495.720 1609.810 2496.690 ;
        RECT 1610.650 2495.720 1613.030 2496.690 ;
        RECT 1613.870 2495.720 1616.250 2496.690 ;
        RECT 1617.090 2495.720 1619.470 2496.690 ;
        RECT 1620.310 2495.720 1622.690 2496.690 ;
        RECT 1623.530 2495.720 1625.910 2496.690 ;
        RECT 1626.750 2495.720 1629.130 2496.690 ;
        RECT 1629.970 2495.720 1632.350 2496.690 ;
        RECT 1633.190 2495.720 1635.570 2496.690 ;
        RECT 1636.410 2495.720 1638.790 2496.690 ;
        RECT 1639.630 2495.720 1642.010 2496.690 ;
        RECT 1642.850 2495.720 1645.230 2496.690 ;
        RECT 1646.070 2495.720 1648.450 2496.690 ;
        RECT 1649.290 2495.720 1651.670 2496.690 ;
        RECT 1652.510 2495.720 1654.890 2496.690 ;
        RECT 1655.730 2495.720 1658.110 2496.690 ;
        RECT 1658.950 2495.720 1661.330 2496.690 ;
        RECT 1662.170 2495.720 1664.550 2496.690 ;
        RECT 1665.390 2495.720 1667.770 2496.690 ;
        RECT 1668.610 2495.720 1670.990 2496.690 ;
        RECT 1671.830 2495.720 1674.210 2496.690 ;
        RECT 1675.050 2495.720 1677.430 2496.690 ;
        RECT 1678.270 2495.720 1680.650 2496.690 ;
        RECT 1681.490 2495.720 1683.870 2496.690 ;
        RECT 1684.710 2495.720 1687.090 2496.690 ;
        RECT 1687.930 2495.720 1690.310 2496.690 ;
        RECT 1691.150 2495.720 1693.530 2496.690 ;
        RECT 1694.370 2495.720 1696.750 2496.690 ;
        RECT 1697.590 2495.720 1699.970 2496.690 ;
        RECT 1700.810 2495.720 1703.190 2496.690 ;
        RECT 1704.030 2495.720 1706.410 2496.690 ;
        RECT 1707.250 2495.720 1709.630 2496.690 ;
        RECT 1710.470 2495.720 1712.850 2496.690 ;
        RECT 1713.690 2495.720 1716.070 2496.690 ;
        RECT 1716.910 2495.720 1719.290 2496.690 ;
        RECT 1720.130 2495.720 1722.510 2496.690 ;
        RECT 1723.350 2495.720 1725.730 2496.690 ;
        RECT 1726.570 2495.720 1728.950 2496.690 ;
        RECT 1729.790 2495.720 1732.170 2496.690 ;
        RECT 1733.010 2495.720 1735.390 2496.690 ;
        RECT 1736.230 2495.720 1738.610 2496.690 ;
        RECT 1739.450 2495.720 1741.830 2496.690 ;
        RECT 1742.670 2495.720 1745.050 2496.690 ;
        RECT 1745.890 2495.720 1748.270 2496.690 ;
        RECT 1749.110 2495.720 1751.490 2496.690 ;
        RECT 1752.330 2495.720 1754.710 2496.690 ;
        RECT 1755.550 2495.720 1757.930 2496.690 ;
        RECT 1758.770 2495.720 1761.150 2496.690 ;
        RECT 1761.990 2495.720 1764.370 2496.690 ;
        RECT 1765.210 2495.720 1767.590 2496.690 ;
        RECT 1768.430 2495.720 1770.810 2496.690 ;
        RECT 1771.650 2495.720 1774.030 2496.690 ;
        RECT 1774.870 2495.720 1777.250 2496.690 ;
        RECT 1778.090 2495.720 1780.470 2496.690 ;
        RECT 1781.310 2495.720 1783.690 2496.690 ;
        RECT 1784.530 2495.720 1786.910 2496.690 ;
        RECT 1787.750 2495.720 1790.130 2496.690 ;
        RECT 1790.970 2495.720 1793.350 2496.690 ;
        RECT 1794.190 2495.720 1796.570 2496.690 ;
        RECT 1797.410 2495.720 1799.790 2496.690 ;
        RECT 1800.630 2495.720 1803.010 2496.690 ;
        RECT 1803.850 2495.720 1806.230 2496.690 ;
        RECT 1807.070 2495.720 1809.450 2496.690 ;
        RECT 1810.290 2495.720 1812.670 2496.690 ;
        RECT 1813.510 2495.720 1815.890 2496.690 ;
        RECT 1816.730 2495.720 1819.110 2496.690 ;
        RECT 1819.950 2495.720 1822.330 2496.690 ;
        RECT 1823.170 2495.720 1825.550 2496.690 ;
        RECT 1826.390 2495.720 1828.770 2496.690 ;
        RECT 1829.610 2495.720 1831.990 2496.690 ;
        RECT 1832.830 2495.720 1835.210 2496.690 ;
        RECT 1836.050 2495.720 1838.430 2496.690 ;
        RECT 1839.270 2495.720 1841.650 2496.690 ;
        RECT 1842.490 2495.720 1844.870 2496.690 ;
        RECT 1845.710 2495.720 1848.090 2496.690 ;
        RECT 1848.930 2495.720 1851.310 2496.690 ;
        RECT 1852.150 2495.720 1854.530 2496.690 ;
        RECT 1855.370 2495.720 2492.650 2496.690 ;
        RECT 4.230 10.695 2492.650 2495.720 ;
      LAYER met3 ;
        RECT 3.950 1820.040 2496.000 2488.965 ;
        RECT 4.400 1818.640 2496.000 1820.040 ;
        RECT 3.950 1816.640 2496.000 1818.640 ;
        RECT 4.400 1815.240 2496.000 1816.640 ;
        RECT 3.950 1813.240 2496.000 1815.240 ;
        RECT 4.400 1811.840 2496.000 1813.240 ;
        RECT 3.950 1809.840 2496.000 1811.840 ;
        RECT 4.400 1808.440 2496.000 1809.840 ;
        RECT 3.950 1806.440 2496.000 1808.440 ;
        RECT 4.400 1805.040 2496.000 1806.440 ;
        RECT 3.950 1803.040 2496.000 1805.040 ;
        RECT 4.400 1801.640 2496.000 1803.040 ;
        RECT 3.950 1799.640 2496.000 1801.640 ;
        RECT 4.400 1798.240 2496.000 1799.640 ;
        RECT 3.950 1796.240 2496.000 1798.240 ;
        RECT 4.400 1794.840 2496.000 1796.240 ;
        RECT 3.950 1792.840 2496.000 1794.840 ;
        RECT 4.400 1791.440 2496.000 1792.840 ;
        RECT 3.950 1789.440 2496.000 1791.440 ;
        RECT 4.400 1788.040 2496.000 1789.440 ;
        RECT 3.950 1786.040 2496.000 1788.040 ;
        RECT 4.400 1784.640 2496.000 1786.040 ;
        RECT 3.950 1782.640 2496.000 1784.640 ;
        RECT 4.400 1781.240 2496.000 1782.640 ;
        RECT 3.950 1779.240 2496.000 1781.240 ;
        RECT 4.400 1777.840 2496.000 1779.240 ;
        RECT 3.950 1775.840 2496.000 1777.840 ;
        RECT 4.400 1774.440 2496.000 1775.840 ;
        RECT 3.950 1772.440 2496.000 1774.440 ;
        RECT 4.400 1771.040 2496.000 1772.440 ;
        RECT 3.950 1769.040 2496.000 1771.040 ;
        RECT 4.400 1767.640 2496.000 1769.040 ;
        RECT 3.950 1765.640 2496.000 1767.640 ;
        RECT 4.400 1764.240 2496.000 1765.640 ;
        RECT 3.950 1619.440 2496.000 1764.240 ;
        RECT 3.950 1618.040 2495.600 1619.440 ;
        RECT 3.950 1616.040 2496.000 1618.040 ;
        RECT 3.950 1614.640 2495.600 1616.040 ;
        RECT 3.950 1612.640 2496.000 1614.640 ;
        RECT 3.950 1611.240 2495.600 1612.640 ;
        RECT 3.950 1609.240 2496.000 1611.240 ;
        RECT 3.950 1607.840 2495.600 1609.240 ;
        RECT 3.950 1605.840 2496.000 1607.840 ;
        RECT 3.950 1604.440 2495.600 1605.840 ;
        RECT 3.950 1602.440 2496.000 1604.440 ;
        RECT 3.950 1601.040 2495.600 1602.440 ;
        RECT 3.950 1592.240 2496.000 1601.040 ;
        RECT 3.950 1590.840 2495.600 1592.240 ;
        RECT 3.950 1588.840 2496.000 1590.840 ;
        RECT 3.950 1587.440 2495.600 1588.840 ;
        RECT 3.950 1585.440 2496.000 1587.440 ;
        RECT 3.950 1584.040 2495.600 1585.440 ;
        RECT 3.950 1575.240 2496.000 1584.040 ;
        RECT 3.950 1573.840 2495.600 1575.240 ;
        RECT 3.950 1571.840 2496.000 1573.840 ;
        RECT 3.950 1570.440 2495.600 1571.840 ;
        RECT 3.950 1565.040 2496.000 1570.440 ;
        RECT 3.950 1563.640 2495.600 1565.040 ;
        RECT 3.950 1558.240 2496.000 1563.640 ;
        RECT 3.950 1556.840 2495.600 1558.240 ;
        RECT 3.950 1554.840 2496.000 1556.840 ;
        RECT 3.950 1553.440 2495.600 1554.840 ;
        RECT 3.950 1551.440 2496.000 1553.440 ;
        RECT 3.950 1550.040 2495.600 1551.440 ;
        RECT 3.950 1548.040 2496.000 1550.040 ;
        RECT 3.950 1546.640 2495.600 1548.040 ;
        RECT 3.950 1544.640 2496.000 1546.640 ;
        RECT 3.950 1543.240 2495.600 1544.640 ;
        RECT 3.950 1541.240 2496.000 1543.240 ;
        RECT 3.950 1539.840 2495.600 1541.240 ;
        RECT 3.950 1537.840 2496.000 1539.840 ;
        RECT 3.950 1536.440 2495.600 1537.840 ;
        RECT 3.950 1534.440 2496.000 1536.440 ;
        RECT 3.950 1533.040 2495.600 1534.440 ;
        RECT 3.950 1507.240 2496.000 1533.040 ;
        RECT 4.400 1505.840 2496.000 1507.240 ;
        RECT 3.950 1503.840 2496.000 1505.840 ;
        RECT 4.400 1502.440 2496.000 1503.840 ;
        RECT 3.950 1500.440 2496.000 1502.440 ;
        RECT 4.400 1499.040 2496.000 1500.440 ;
        RECT 3.950 1497.040 2496.000 1499.040 ;
        RECT 4.400 1495.640 2496.000 1497.040 ;
        RECT 3.950 1493.640 2496.000 1495.640 ;
        RECT 4.400 1492.240 2496.000 1493.640 ;
        RECT 3.950 1490.240 2496.000 1492.240 ;
        RECT 4.400 1488.840 2496.000 1490.240 ;
        RECT 3.950 1486.840 2496.000 1488.840 ;
        RECT 4.400 1485.440 2496.000 1486.840 ;
        RECT 3.950 1483.440 2496.000 1485.440 ;
        RECT 4.400 1482.040 2496.000 1483.440 ;
        RECT 3.950 1480.040 2496.000 1482.040 ;
        RECT 4.400 1478.640 2496.000 1480.040 ;
        RECT 3.950 1476.640 2496.000 1478.640 ;
        RECT 4.400 1475.240 2496.000 1476.640 ;
        RECT 3.950 1473.240 2496.000 1475.240 ;
        RECT 4.400 1471.840 2496.000 1473.240 ;
        RECT 3.950 1469.840 2496.000 1471.840 ;
        RECT 4.400 1468.440 2496.000 1469.840 ;
        RECT 3.950 1466.440 2496.000 1468.440 ;
        RECT 4.400 1465.040 2496.000 1466.440 ;
        RECT 3.950 1463.040 2496.000 1465.040 ;
        RECT 4.400 1461.640 2496.000 1463.040 ;
        RECT 3.950 1459.640 2496.000 1461.640 ;
        RECT 4.400 1458.240 2496.000 1459.640 ;
        RECT 3.950 1456.240 2496.000 1458.240 ;
        RECT 4.400 1454.840 2496.000 1456.240 ;
        RECT 3.950 1452.840 2496.000 1454.840 ;
        RECT 4.400 1451.440 2496.000 1452.840 ;
        RECT 3.950 1449.440 2496.000 1451.440 ;
        RECT 4.400 1448.040 2496.000 1449.440 ;
        RECT 3.950 1446.040 2496.000 1448.040 ;
        RECT 4.400 1444.640 2496.000 1446.040 ;
        RECT 3.950 1442.640 2496.000 1444.640 ;
        RECT 4.400 1441.240 2496.000 1442.640 ;
        RECT 3.950 1439.240 2496.000 1441.240 ;
        RECT 4.400 1437.840 2496.000 1439.240 ;
        RECT 3.950 1435.840 2496.000 1437.840 ;
        RECT 4.400 1434.440 2496.000 1435.840 ;
        RECT 3.950 1432.440 2496.000 1434.440 ;
        RECT 4.400 1431.040 2496.000 1432.440 ;
        RECT 3.950 1429.040 2496.000 1431.040 ;
        RECT 4.400 1427.640 2495.600 1429.040 ;
        RECT 3.950 1425.640 2496.000 1427.640 ;
        RECT 4.400 1424.240 2496.000 1425.640 ;
        RECT 3.950 1422.240 2496.000 1424.240 ;
        RECT 4.400 1420.840 2496.000 1422.240 ;
        RECT 3.950 1418.840 2496.000 1420.840 ;
        RECT 4.400 1417.440 2495.600 1418.840 ;
        RECT 3.950 1415.440 2496.000 1417.440 ;
        RECT 4.400 1414.040 2496.000 1415.440 ;
        RECT 3.950 1412.040 2496.000 1414.040 ;
        RECT 4.400 1410.640 2496.000 1412.040 ;
        RECT 3.950 1408.640 2496.000 1410.640 ;
        RECT 4.400 1407.240 2496.000 1408.640 ;
        RECT 3.950 1405.240 2496.000 1407.240 ;
        RECT 4.400 1403.840 2496.000 1405.240 ;
        RECT 3.950 1401.840 2496.000 1403.840 ;
        RECT 4.400 1400.440 2496.000 1401.840 ;
        RECT 3.950 1398.440 2496.000 1400.440 ;
        RECT 4.400 1397.040 2496.000 1398.440 ;
        RECT 3.950 1395.040 2496.000 1397.040 ;
        RECT 4.400 1393.640 2496.000 1395.040 ;
        RECT 3.950 1391.640 2496.000 1393.640 ;
        RECT 4.400 1390.240 2495.600 1391.640 ;
        RECT 3.950 1388.240 2496.000 1390.240 ;
        RECT 4.400 1386.840 2495.600 1388.240 ;
        RECT 3.950 1384.840 2496.000 1386.840 ;
        RECT 4.400 1383.440 2496.000 1384.840 ;
        RECT 3.950 1381.440 2496.000 1383.440 ;
        RECT 4.400 1380.040 2495.600 1381.440 ;
        RECT 3.950 1378.040 2496.000 1380.040 ;
        RECT 4.400 1376.640 2496.000 1378.040 ;
        RECT 3.950 1374.640 2496.000 1376.640 ;
        RECT 4.400 1373.240 2496.000 1374.640 ;
        RECT 3.950 1371.240 2496.000 1373.240 ;
        RECT 4.400 1369.840 2496.000 1371.240 ;
        RECT 3.950 1367.840 2496.000 1369.840 ;
        RECT 4.400 1366.440 2496.000 1367.840 ;
        RECT 3.950 1364.440 2496.000 1366.440 ;
        RECT 4.400 1363.040 2496.000 1364.440 ;
        RECT 3.950 1361.040 2496.000 1363.040 ;
        RECT 4.400 1359.640 2496.000 1361.040 ;
        RECT 3.950 1357.640 2496.000 1359.640 ;
        RECT 4.400 1356.240 2496.000 1357.640 ;
        RECT 3.950 1354.240 2496.000 1356.240 ;
        RECT 4.400 1352.840 2496.000 1354.240 ;
        RECT 3.950 1350.840 2496.000 1352.840 ;
        RECT 4.400 1349.440 2496.000 1350.840 ;
        RECT 3.950 1347.440 2496.000 1349.440 ;
        RECT 4.400 1346.040 2496.000 1347.440 ;
        RECT 3.950 1344.040 2496.000 1346.040 ;
        RECT 4.400 1342.640 2496.000 1344.040 ;
        RECT 3.950 1340.640 2496.000 1342.640 ;
        RECT 4.400 1339.240 2496.000 1340.640 ;
        RECT 3.950 1337.240 2496.000 1339.240 ;
        RECT 4.400 1335.840 2496.000 1337.240 ;
        RECT 3.950 1000.640 2496.000 1335.840 ;
        RECT 3.950 999.240 2495.600 1000.640 ;
        RECT 3.950 993.840 2496.000 999.240 ;
        RECT 3.950 992.440 2495.600 993.840 ;
        RECT 3.950 990.440 2496.000 992.440 ;
        RECT 3.950 989.040 2495.600 990.440 ;
        RECT 3.950 980.240 2496.000 989.040 ;
        RECT 3.950 978.840 2495.600 980.240 ;
        RECT 3.950 976.840 2496.000 978.840 ;
        RECT 3.950 975.440 2495.600 976.840 ;
        RECT 3.950 970.040 2496.000 975.440 ;
        RECT 3.950 968.640 2495.600 970.040 ;
        RECT 3.950 966.640 2496.000 968.640 ;
        RECT 3.950 965.240 2495.600 966.640 ;
        RECT 3.950 963.240 2496.000 965.240 ;
        RECT 3.950 961.840 2495.600 963.240 ;
        RECT 3.950 959.840 2496.000 961.840 ;
        RECT 3.950 958.440 2495.600 959.840 ;
        RECT 3.950 735.440 2496.000 958.440 ;
        RECT 3.950 734.040 2495.600 735.440 ;
        RECT 3.950 732.040 2496.000 734.040 ;
        RECT 3.950 730.640 2495.600 732.040 ;
        RECT 3.950 728.640 2496.000 730.640 ;
        RECT 3.950 727.240 2495.600 728.640 ;
        RECT 3.950 725.240 2496.000 727.240 ;
        RECT 3.950 723.840 2495.600 725.240 ;
        RECT 3.950 721.840 2496.000 723.840 ;
        RECT 3.950 720.440 2495.600 721.840 ;
        RECT 3.950 718.440 2496.000 720.440 ;
        RECT 3.950 717.040 2495.600 718.440 ;
        RECT 3.950 715.040 2496.000 717.040 ;
        RECT 3.950 713.640 2495.600 715.040 ;
        RECT 3.950 711.640 2496.000 713.640 ;
        RECT 3.950 710.240 2495.600 711.640 ;
        RECT 3.950 708.240 2496.000 710.240 ;
        RECT 3.950 706.840 2495.600 708.240 ;
        RECT 3.950 704.840 2496.000 706.840 ;
        RECT 3.950 703.440 2495.600 704.840 ;
        RECT 3.950 701.440 2496.000 703.440 ;
        RECT 3.950 700.040 2495.600 701.440 ;
        RECT 3.950 698.040 2496.000 700.040 ;
        RECT 3.950 696.640 2495.600 698.040 ;
        RECT 3.950 694.640 2496.000 696.640 ;
        RECT 3.950 693.240 2495.600 694.640 ;
        RECT 3.950 691.240 2496.000 693.240 ;
        RECT 3.950 689.840 2495.600 691.240 ;
        RECT 3.950 687.840 2496.000 689.840 ;
        RECT 3.950 686.440 2495.600 687.840 ;
        RECT 3.950 684.440 2496.000 686.440 ;
        RECT 3.950 683.040 2495.600 684.440 ;
        RECT 3.950 681.040 2496.000 683.040 ;
        RECT 3.950 679.640 2495.600 681.040 ;
        RECT 3.950 10.715 2496.000 679.640 ;
      LAYER met4 ;
        RECT 3.975 689.695 20.640 2487.265 ;
        RECT 23.040 689.695 23.940 2487.265 ;
        RECT 26.340 689.695 174.240 2487.265 ;
        RECT 176.640 689.695 177.540 2487.265 ;
        RECT 179.940 689.695 327.840 2487.265 ;
        RECT 330.240 689.695 331.140 2487.265 ;
        RECT 333.540 689.695 481.440 2487.265 ;
        RECT 483.840 689.695 484.740 2487.265 ;
        RECT 487.140 689.695 635.040 2487.265 ;
        RECT 637.440 689.695 638.340 2487.265 ;
        RECT 640.740 689.695 788.640 2487.265 ;
        RECT 791.040 689.695 791.940 2487.265 ;
        RECT 794.340 689.695 942.240 2487.265 ;
        RECT 944.640 689.695 945.540 2487.265 ;
        RECT 947.940 689.695 1095.840 2487.265 ;
        RECT 1098.240 689.695 1099.140 2487.265 ;
        RECT 1101.540 689.695 1249.440 2487.265 ;
        RECT 1251.840 689.695 1252.740 2487.265 ;
        RECT 1255.140 689.695 1403.040 2487.265 ;
        RECT 1405.440 689.695 1406.340 2487.265 ;
        RECT 1408.740 689.695 1556.640 2487.265 ;
        RECT 1559.040 689.695 1559.940 2487.265 ;
        RECT 1562.340 689.695 1710.240 2487.265 ;
        RECT 1712.640 689.695 1713.540 2487.265 ;
        RECT 1715.940 689.695 1863.840 2487.265 ;
        RECT 1866.240 689.695 1867.140 2487.265 ;
        RECT 1869.540 689.695 2017.440 2487.265 ;
        RECT 2019.840 689.695 2020.740 2487.265 ;
        RECT 2023.140 689.695 2171.040 2487.265 ;
        RECT 2173.440 689.695 2174.340 2487.265 ;
        RECT 2176.740 689.695 2314.425 2487.265 ;
  END
END svm_compute_core
END LIBRARY

